VERSION 5.7 ;
BUSBITCHARS "[]" ;
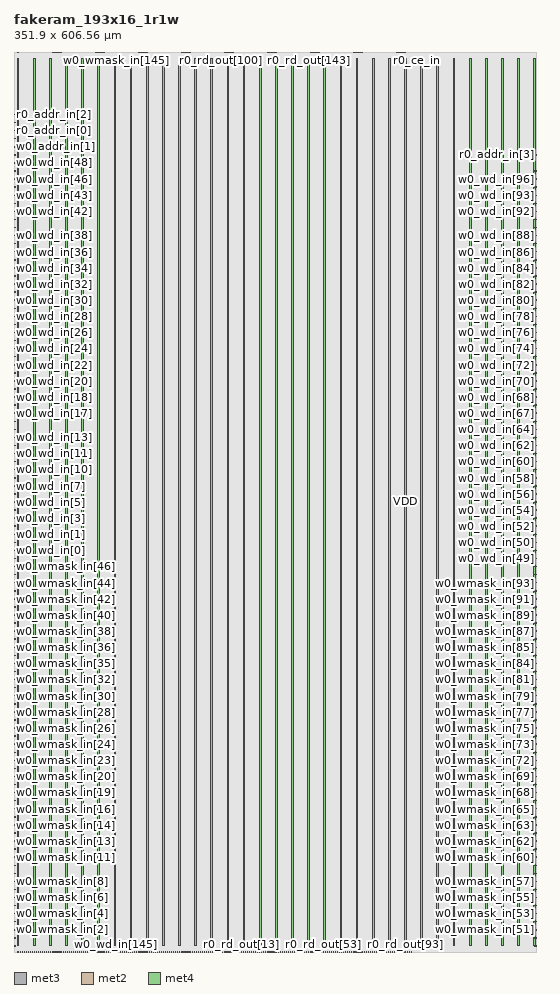
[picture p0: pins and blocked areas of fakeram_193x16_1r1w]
MACRO fakeram_193x16_1r1w
  FOREIGN fakeram_193x16_1r1w 0 0 ;
  SYMMETRY X Y R90 ;
  SIZE 351.900 BY 606.560 ;
  CLASS BLOCK ;
  PIN w0_wmask_in[0]
    DIRECTION INPUT ;
    USE SIGNAL ;
    SHAPE ABUTMENT ;
    PORT
      LAYER met3 ;
      RECT 0.000 3.930 0.900 4.230 ;
    END
  END w0_wmask_in[0]
  PIN w0_wmask_in[1]
    DIRECTION INPUT ;
    USE SIGNAL ;
    SHAPE ABUTMENT ;
    PORT
      LAYER met3 ;
      RECT 0.000 9.370 0.900 9.670 ;
    END
  END w0_wmask_in[1]
  PIN w0_wmask_in[2]
    DIRECTION INPUT ;
    USE SIGNAL ;
    SHAPE ABUTMENT ;
    PORT
      LAYER met3 ;
      RECT 0.000 14.810 0.900 15.110 ;
    END
  END w0_wmask_in[2]
  PIN w0_wmask_in[3]
    DIRECTION INPUT ;
    USE SIGNAL ;
    SHAPE ABUTMENT ;
    PORT
      LAYER met3 ;
      RECT 0.000 20.250 0.900 20.550 ;
    END
  END w0_wmask_in[3]
  PIN w0_wmask_in[4]
    DIRECTION INPUT ;
    USE SIGNAL ;
    SHAPE ABUTMENT ;
    PORT
      LAYER met3 ;
      RECT 0.000 25.690 0.900 25.990 ;
    END
  END w0_wmask_in[4]
  PIN w0_wmask_in[5]
    DIRECTION INPUT ;
    USE SIGNAL ;
    SHAPE ABUTMENT ;
    PORT
      LAYER met3 ;
      RECT 0.000 31.130 0.900 31.430 ;
    END
  END w0_wmask_in[5]
  PIN w0_wmask_in[6]
    DIRECTION INPUT ;
    USE SIGNAL ;
    SHAPE ABUTMENT ;
    PORT
      LAYER met3 ;
      RECT 0.000 36.570 0.900 36.870 ;
    END
  END w0_wmask_in[6]
  PIN w0_wmask_in[7]
    DIRECTION INPUT ;
    USE SIGNAL ;
    SHAPE ABUTMENT ;
    PORT
      LAYER met3 ;
      RECT 0.000 42.010 0.900 42.310 ;
    END
  END w0_wmask_in[7]
  PIN w0_wmask_in[8]
    DIRECTION INPUT ;
    USE SIGNAL ;
    SHAPE ABUTMENT ;
    PORT
      LAYER met3 ;
      RECT 0.000 47.450 0.900 47.750 ;
    END
  END w0_wmask_in[8]
  PIN w0_wmask_in[9]
    DIRECTION INPUT ;
    USE SIGNAL ;
    SHAPE ABUTMENT ;
    PORT
      LAYER met3 ;
      RECT 0.000 52.890 0.900 53.190 ;
    END
  END w0_wmask_in[9]
  PIN w0_wmask_in[10]
    DIRECTION INPUT ;
    USE SIGNAL ;
    SHAPE ABUTMENT ;
    PORT
      LAYER met3 ;
      RECT 0.000 58.330 0.900 58.630 ;
    END
  END w0_wmask_in[10]
  PIN w0_wmask_in[11]
    DIRECTION INPUT ;
    USE SIGNAL ;
    SHAPE ABUTMENT ;
    PORT
      LAYER met3 ;
      RECT 0.000 63.770 0.900 64.070 ;
    END
  END w0_wmask_in[11]
  PIN w0_wmask_in[12]
    DIRECTION INPUT ;
    USE SIGNAL ;
    SHAPE ABUTMENT ;
    PORT
      LAYER met3 ;
      RECT 0.000 69.210 0.900 69.510 ;
    END
  END w0_wmask_in[12]
  PIN w0_wmask_in[13]
    DIRECTION INPUT ;
    USE SIGNAL ;
    SHAPE ABUTMENT ;
    PORT
      LAYER met3 ;
      RECT 0.000 74.650 0.900 74.950 ;
    END
  END w0_wmask_in[13]
  PIN w0_wmask_in[14]
    DIRECTION INPUT ;
    USE SIGNAL ;
    SHAPE ABUTMENT ;
    PORT
      LAYER met3 ;
      RECT 0.000 80.090 0.900 80.390 ;
    END
  END w0_wmask_in[14]
  PIN w0_wmask_in[15]
    DIRECTION INPUT ;
    USE SIGNAL ;
    SHAPE ABUTMENT ;
    PORT
      LAYER met3 ;
      RECT 0.000 85.530 0.900 85.830 ;
    END
  END w0_wmask_in[15]
  PIN w0_wmask_in[16]
    DIRECTION INPUT ;
    USE SIGNAL ;
    SHAPE ABUTMENT ;
    PORT
      LAYER met3 ;
      RECT 0.000 90.970 0.900 91.270 ;
    END
  END w0_wmask_in[16]
  PIN w0_wmask_in[17]
    DIRECTION INPUT ;
    USE SIGNAL ;
    SHAPE ABUTMENT ;
    PORT
      LAYER met3 ;
      RECT 0.000 96.410 0.900 96.710 ;
    END
  END w0_wmask_in[17]
  PIN w0_wmask_in[18]
    DIRECTION INPUT ;
    USE SIGNAL ;
    SHAPE ABUTMENT ;
    PORT
      LAYER met3 ;
      RECT 0.000 101.850 0.900 102.150 ;
    END
  END w0_wmask_in[18]
  PIN w0_wmask_in[19]
    DIRECTION INPUT ;
    USE SIGNAL ;
    SHAPE ABUTMENT ;
    PORT
      LAYER met3 ;
      RECT 0.000 107.290 0.900 107.590 ;
    END
  END w0_wmask_in[19]
  PIN w0_wmask_in[20]
    DIRECTION INPUT ;
    USE SIGNAL ;
    SHAPE ABUTMENT ;
    PORT
      LAYER met3 ;
      RECT 0.000 112.730 0.900 113.030 ;
    END
  END w0_wmask_in[20]
  PIN w0_wmask_in[21]
    DIRECTION INPUT ;
    USE SIGNAL ;
    SHAPE ABUTMENT ;
    PORT
      LAYER met3 ;
      RECT 0.000 118.170 0.900 118.470 ;
    END
  END w0_wmask_in[21]
  PIN w0_wmask_in[22]
    DIRECTION INPUT ;
    USE SIGNAL ;
    SHAPE ABUTMENT ;
    PORT
      LAYER met3 ;
      RECT 0.000 123.610 0.900 123.910 ;
    END
  END w0_wmask_in[22]
  PIN w0_wmask_in[23]
    DIRECTION INPUT ;
    USE SIGNAL ;
    SHAPE ABUTMENT ;
    PORT
      LAYER met3 ;
      RECT 0.000 129.050 0.900 129.350 ;
    END
  END w0_wmask_in[23]
  PIN w0_wmask_in[24]
    DIRECTION INPUT ;
    USE SIGNAL ;
    SHAPE ABUTMENT ;
    PORT
      LAYER met3 ;
      RECT 0.000 134.490 0.900 134.790 ;
    END
  END w0_wmask_in[24]
  PIN w0_wmask_in[25]
    DIRECTION INPUT ;
    USE SIGNAL ;
    SHAPE ABUTMENT ;
    PORT
      LAYER met3 ;
      RECT 0.000 139.930 0.900 140.230 ;
    END
  END w0_wmask_in[25]
  PIN w0_wmask_in[26]
    DIRECTION INPUT ;
    USE SIGNAL ;
    SHAPE ABUTMENT ;
    PORT
      LAYER met3 ;
      RECT 0.000 145.370 0.900 145.670 ;
    END
  END w0_wmask_in[26]
  PIN w0_wmask_in[27]
    DIRECTION INPUT ;
    USE SIGNAL ;
    SHAPE ABUTMENT ;
    PORT
      LAYER met3 ;
      RECT 0.000 150.810 0.900 151.110 ;
    END
  END w0_wmask_in[27]
  PIN w0_wmask_in[28]
    DIRECTION INPUT ;
    USE SIGNAL ;
    SHAPE ABUTMENT ;
    PORT
      LAYER met3 ;
      RECT 0.000 156.250 0.900 156.550 ;
    END
  END w0_wmask_in[28]
  PIN w0_wmask_in[29]
    DIRECTION INPUT ;
    USE SIGNAL ;
    SHAPE ABUTMENT ;
    PORT
      LAYER met3 ;
      RECT 0.000 161.690 0.900 161.990 ;
    END
  END w0_wmask_in[29]
  PIN w0_wmask_in[30]
    DIRECTION INPUT ;
    USE SIGNAL ;
    SHAPE ABUTMENT ;
    PORT
      LAYER met3 ;
      RECT 0.000 167.130 0.900 167.430 ;
    END
  END w0_wmask_in[30]
  PIN w0_wmask_in[31]
    DIRECTION INPUT ;
    USE SIGNAL ;
    SHAPE ABUTMENT ;
    PORT
      LAYER met3 ;
      RECT 0.000 172.570 0.900 172.870 ;
    END
  END w0_wmask_in[31]
  PIN w0_wmask_in[32]
    DIRECTION INPUT ;
    USE SIGNAL ;
    SHAPE ABUTMENT ;
    PORT
      LAYER met3 ;
      RECT 0.000 178.010 0.900 178.310 ;
    END
  END w0_wmask_in[32]
  PIN w0_wmask_in[33]
    DIRECTION INPUT ;
    USE SIGNAL ;
    SHAPE ABUTMENT ;
    PORT
      LAYER met3 ;
      RECT 0.000 183.450 0.900 183.750 ;
    END
  END w0_wmask_in[33]
  PIN w0_wmask_in[34]
    DIRECTION INPUT ;
    USE SIGNAL ;
    SHAPE ABUTMENT ;
    PORT
      LAYER met3 ;
      RECT 0.000 188.890 0.900 189.190 ;
    END
  END w0_wmask_in[34]
  PIN w0_wmask_in[35]
    DIRECTION INPUT ;
    USE SIGNAL ;
    SHAPE ABUTMENT ;
    PORT
      LAYER met3 ;
      RECT 0.000 194.330 0.900 194.630 ;
    END
  END w0_wmask_in[35]
  PIN w0_wmask_in[36]
    DIRECTION INPUT ;
    USE SIGNAL ;
    SHAPE ABUTMENT ;
    PORT
      LAYER met3 ;
      RECT 0.000 199.770 0.900 200.070 ;
    END
  END w0_wmask_in[36]
  PIN w0_wmask_in[37]
    DIRECTION INPUT ;
    USE SIGNAL ;
    SHAPE ABUTMENT ;
    PORT
      LAYER met3 ;
      RECT 0.000 205.210 0.900 205.510 ;
    END
  END w0_wmask_in[37]
  PIN w0_wmask_in[38]
    DIRECTION INPUT ;
    USE SIGNAL ;
    SHAPE ABUTMENT ;
    PORT
      LAYER met3 ;
      RECT 0.000 210.650 0.900 210.950 ;
    END
  END w0_wmask_in[38]
  PIN w0_wmask_in[39]
    DIRECTION INPUT ;
    USE SIGNAL ;
    SHAPE ABUTMENT ;
    PORT
      LAYER met3 ;
      RECT 0.000 216.090 0.900 216.390 ;
    END
  END w0_wmask_in[39]
  PIN w0_wmask_in[40]
    DIRECTION INPUT ;
    USE SIGNAL ;
    SHAPE ABUTMENT ;
    PORT
      LAYER met3 ;
      RECT 0.000 221.530 0.900 221.830 ;
    END
  END w0_wmask_in[40]
  PIN w0_wmask_in[41]
    DIRECTION INPUT ;
    USE SIGNAL ;
    SHAPE ABUTMENT ;
    PORT
      LAYER met3 ;
      RECT 0.000 226.970 0.900 227.270 ;
    END
  END w0_wmask_in[41]
  PIN w0_wmask_in[42]
    DIRECTION INPUT ;
    USE SIGNAL ;
    SHAPE ABUTMENT ;
    PORT
      LAYER met3 ;
      RECT 0.000 232.410 0.900 232.710 ;
    END
  END w0_wmask_in[42]
  PIN w0_wmask_in[43]
    DIRECTION INPUT ;
    USE SIGNAL ;
    SHAPE ABUTMENT ;
    PORT
      LAYER met3 ;
      RECT 0.000 237.850 0.900 238.150 ;
    END
  END w0_wmask_in[43]
  PIN w0_wmask_in[44]
    DIRECTION INPUT ;
    USE SIGNAL ;
    SHAPE ABUTMENT ;
    PORT
      LAYER met3 ;
      RECT 0.000 243.290 0.900 243.590 ;
    END
  END w0_wmask_in[44]
  PIN w0_wmask_in[45]
    DIRECTION INPUT ;
    USE SIGNAL ;
    SHAPE ABUTMENT ;
    PORT
      LAYER met3 ;
      RECT 0.000 248.730 0.900 249.030 ;
    END
  END w0_wmask_in[45]
  PIN w0_wmask_in[46]
    DIRECTION INPUT ;
    USE SIGNAL ;
    SHAPE ABUTMENT ;
    PORT
      LAYER met3 ;
      RECT 0.000 254.170 0.900 254.470 ;
    END
  END w0_wmask_in[46]
  PIN w0_wmask_in[47]
    DIRECTION INPUT ;
    USE SIGNAL ;
    SHAPE ABUTMENT ;
    PORT
      LAYER met3 ;
      RECT 0.000 259.610 0.900 259.910 ;
    END
  END w0_wmask_in[47]
  PIN w0_wmask_in[48]
    DIRECTION INPUT ;
    USE SIGNAL ;
    SHAPE ABUTMENT ;
    PORT
      LAYER met3 ;
      RECT 0.000 265.050 0.900 265.350 ;
    END
  END w0_wmask_in[48]
  PIN w0_wmask_in[49]
    DIRECTION INPUT ;
    USE SIGNAL ;
    SHAPE ABUTMENT ;
    PORT
      LAYER met3 ;
      RECT 351.000 3.930 351.900 4.230 ;
    END
  END w0_wmask_in[49]
  PIN w0_wmask_in[50]
    DIRECTION INPUT ;
    USE SIGNAL ;
    SHAPE ABUTMENT ;
    PORT
      LAYER met3 ;
      RECT 351.000 9.370 351.900 9.670 ;
    END
  END w0_wmask_in[50]
  PIN w0_wmask_in[51]
    DIRECTION INPUT ;
    USE SIGNAL ;
    SHAPE ABUTMENT ;
    PORT
      LAYER met3 ;
      RECT 351.000 14.810 351.900 15.110 ;
    END
  END w0_wmask_in[51]
  PIN w0_wmask_in[52]
    DIRECTION INPUT ;
    USE SIGNAL ;
    SHAPE ABUTMENT ;
    PORT
      LAYER met3 ;
      RECT 351.000 20.250 351.900 20.550 ;
    END
  END w0_wmask_in[52]
  PIN w0_wmask_in[53]
    DIRECTION INPUT ;
    USE SIGNAL ;
    SHAPE ABUTMENT ;
    PORT
      LAYER met3 ;
      RECT 351.000 25.690 351.900 25.990 ;
    END
  END w0_wmask_in[53]
  PIN w0_wmask_in[54]
    DIRECTION INPUT ;
    USE SIGNAL ;
    SHAPE ABUTMENT ;
    PORT
      LAYER met3 ;
      RECT 351.000 31.130 351.900 31.430 ;
    END
  END w0_wmask_in[54]
  PIN w0_wmask_in[55]
    DIRECTION INPUT ;
    USE SIGNAL ;
    SHAPE ABUTMENT ;
    PORT
      LAYER met3 ;
      RECT 351.000 36.570 351.900 36.870 ;
    END
  END w0_wmask_in[55]
  PIN w0_wmask_in[56]
    DIRECTION INPUT ;
    USE SIGNAL ;
    SHAPE ABUTMENT ;
    PORT
      LAYER met3 ;
      RECT 351.000 42.010 351.900 42.310 ;
    END
  END w0_wmask_in[56]
  PIN w0_wmask_in[57]
    DIRECTION INPUT ;
    USE SIGNAL ;
    SHAPE ABUTMENT ;
    PORT
      LAYER met3 ;
      RECT 351.000 47.450 351.900 47.750 ;
    END
  END w0_wmask_in[57]
  PIN w0_wmask_in[58]
    DIRECTION INPUT ;
    USE SIGNAL ;
    SHAPE ABUTMENT ;
    PORT
      LAYER met3 ;
      RECT 351.000 52.890 351.900 53.190 ;
    END
  END w0_wmask_in[58]
  PIN w0_wmask_in[59]
    DIRECTION INPUT ;
    USE SIGNAL ;
    SHAPE ABUTMENT ;
    PORT
      LAYER met3 ;
      RECT 351.000 58.330 351.900 58.630 ;
    END
  END w0_wmask_in[59]
  PIN w0_wmask_in[60]
    DIRECTION INPUT ;
    USE SIGNAL ;
    SHAPE ABUTMENT ;
    PORT
      LAYER met3 ;
      RECT 351.000 63.770 351.900 64.070 ;
    END
  END w0_wmask_in[60]
  PIN w0_wmask_in[61]
    DIRECTION INPUT ;
    USE SIGNAL ;
    SHAPE ABUTMENT ;
    PORT
      LAYER met3 ;
      RECT 351.000 69.210 351.900 69.510 ;
    END
  END w0_wmask_in[61]
  PIN w0_wmask_in[62]
    DIRECTION INPUT ;
    USE SIGNAL ;
    SHAPE ABUTMENT ;
    PORT
      LAYER met3 ;
      RECT 351.000 74.650 351.900 74.950 ;
    END
  END w0_wmask_in[62]
  PIN w0_wmask_in[63]
    DIRECTION INPUT ;
    USE SIGNAL ;
    SHAPE ABUTMENT ;
    PORT
      LAYER met3 ;
      RECT 351.000 80.090 351.900 80.390 ;
    END
  END w0_wmask_in[63]
  PIN w0_wmask_in[64]
    DIRECTION INPUT ;
    USE SIGNAL ;
    SHAPE ABUTMENT ;
    PORT
      LAYER met3 ;
      RECT 351.000 85.530 351.900 85.830 ;
    END
  END w0_wmask_in[64]
  PIN w0_wmask_in[65]
    DIRECTION INPUT ;
    USE SIGNAL ;
    SHAPE ABUTMENT ;
    PORT
      LAYER met3 ;
      RECT 351.000 90.970 351.900 91.270 ;
    END
  END w0_wmask_in[65]
  PIN w0_wmask_in[66]
    DIRECTION INPUT ;
    USE SIGNAL ;
    SHAPE ABUTMENT ;
    PORT
      LAYER met3 ;
      RECT 351.000 96.410 351.900 96.710 ;
    END
  END w0_wmask_in[66]
  PIN w0_wmask_in[67]
    DIRECTION INPUT ;
    USE SIGNAL ;
    SHAPE ABUTMENT ;
    PORT
      LAYER met3 ;
      RECT 351.000 101.850 351.900 102.150 ;
    END
  END w0_wmask_in[67]
  PIN w0_wmask_in[68]
    DIRECTION INPUT ;
    USE SIGNAL ;
    SHAPE ABUTMENT ;
    PORT
      LAYER met3 ;
      RECT 351.000 107.290 351.900 107.590 ;
    END
  END w0_wmask_in[68]
  PIN w0_wmask_in[69]
    DIRECTION INPUT ;
    USE SIGNAL ;
    SHAPE ABUTMENT ;
    PORT
      LAYER met3 ;
      RECT 351.000 112.730 351.900 113.030 ;
    END
  END w0_wmask_in[69]
  PIN w0_wmask_in[70]
    DIRECTION INPUT ;
    USE SIGNAL ;
    SHAPE ABUTMENT ;
    PORT
      LAYER met3 ;
      RECT 351.000 118.170 351.900 118.470 ;
    END
  END w0_wmask_in[70]
  PIN w0_wmask_in[71]
    DIRECTION INPUT ;
    USE SIGNAL ;
    SHAPE ABUTMENT ;
    PORT
      LAYER met3 ;
      RECT 351.000 123.610 351.900 123.910 ;
    END
  END w0_wmask_in[71]
  PIN w0_wmask_in[72]
    DIRECTION INPUT ;
    USE SIGNAL ;
    SHAPE ABUTMENT ;
    PORT
      LAYER met3 ;
      RECT 351.000 129.050 351.900 129.350 ;
    END
  END w0_wmask_in[72]
  PIN w0_wmask_in[73]
    DIRECTION INPUT ;
    USE SIGNAL ;
    SHAPE ABUTMENT ;
    PORT
      LAYER met3 ;
      RECT 351.000 134.490 351.900 134.790 ;
    END
  END w0_wmask_in[73]
  PIN w0_wmask_in[74]
    DIRECTION INPUT ;
    USE SIGNAL ;
    SHAPE ABUTMENT ;
    PORT
      LAYER met3 ;
      RECT 351.000 139.930 351.900 140.230 ;
    END
  END w0_wmask_in[74]
  PIN w0_wmask_in[75]
    DIRECTION INPUT ;
    USE SIGNAL ;
    SHAPE ABUTMENT ;
    PORT
      LAYER met3 ;
      RECT 351.000 145.370 351.900 145.670 ;
    END
  END w0_wmask_in[75]
  PIN w0_wmask_in[76]
    DIRECTION INPUT ;
    USE SIGNAL ;
    SHAPE ABUTMENT ;
    PORT
      LAYER met3 ;
      RECT 351.000 150.810 351.900 151.110 ;
    END
  END w0_wmask_in[76]
  PIN w0_wmask_in[77]
    DIRECTION INPUT ;
    USE SIGNAL ;
    SHAPE ABUTMENT ;
    PORT
      LAYER met3 ;
      RECT 351.000 156.250 351.900 156.550 ;
    END
  END w0_wmask_in[77]
  PIN w0_wmask_in[78]
    DIRECTION INPUT ;
    USE SIGNAL ;
    SHAPE ABUTMENT ;
    PORT
      LAYER met3 ;
      RECT 351.000 161.690 351.900 161.990 ;
    END
  END w0_wmask_in[78]
  PIN w0_wmask_in[79]
    DIRECTION INPUT ;
    USE SIGNAL ;
    SHAPE ABUTMENT ;
    PORT
      LAYER met3 ;
      RECT 351.000 167.130 351.900 167.430 ;
    END
  END w0_wmask_in[79]
  PIN w0_wmask_in[80]
    DIRECTION INPUT ;
    USE SIGNAL ;
    SHAPE ABUTMENT ;
    PORT
      LAYER met3 ;
      RECT 351.000 172.570 351.900 172.870 ;
    END
  END w0_wmask_in[80]
  PIN w0_wmask_in[81]
    DIRECTION INPUT ;
    USE SIGNAL ;
    SHAPE ABUTMENT ;
    PORT
      LAYER met3 ;
      RECT 351.000 178.010 351.900 178.310 ;
    END
  END w0_wmask_in[81]
  PIN w0_wmask_in[82]
    DIRECTION INPUT ;
    USE SIGNAL ;
    SHAPE ABUTMENT ;
    PORT
      LAYER met3 ;
      RECT 351.000 183.450 351.900 183.750 ;
    END
  END w0_wmask_in[82]
  PIN w0_wmask_in[83]
    DIRECTION INPUT ;
    USE SIGNAL ;
    SHAPE ABUTMENT ;
    PORT
      LAYER met3 ;
      RECT 351.000 188.890 351.900 189.190 ;
    END
  END w0_wmask_in[83]
  PIN w0_wmask_in[84]
    DIRECTION INPUT ;
    USE SIGNAL ;
    SHAPE ABUTMENT ;
    PORT
      LAYER met3 ;
      RECT 351.000 194.330 351.900 194.630 ;
    END
  END w0_wmask_in[84]
  PIN w0_wmask_in[85]
    DIRECTION INPUT ;
    USE SIGNAL ;
    SHAPE ABUTMENT ;
    PORT
      LAYER met3 ;
      RECT 351.000 199.770 351.900 200.070 ;
    END
  END w0_wmask_in[85]
  PIN w0_wmask_in[86]
    DIRECTION INPUT ;
    USE SIGNAL ;
    SHAPE ABUTMENT ;
    PORT
      LAYER met3 ;
      RECT 351.000 205.210 351.900 205.510 ;
    END
  END w0_wmask_in[86]
  PIN w0_wmask_in[87]
    DIRECTION INPUT ;
    USE SIGNAL ;
    SHAPE ABUTMENT ;
    PORT
      LAYER met3 ;
      RECT 351.000 210.650 351.900 210.950 ;
    END
  END w0_wmask_in[87]
  PIN w0_wmask_in[88]
    DIRECTION INPUT ;
    USE SIGNAL ;
    SHAPE ABUTMENT ;
    PORT
      LAYER met3 ;
      RECT 351.000 216.090 351.900 216.390 ;
    END
  END w0_wmask_in[88]
  PIN w0_wmask_in[89]
    DIRECTION INPUT ;
    USE SIGNAL ;
    SHAPE ABUTMENT ;
    PORT
      LAYER met3 ;
      RECT 351.000 221.530 351.900 221.830 ;
    END
  END w0_wmask_in[89]
  PIN w0_wmask_in[90]
    DIRECTION INPUT ;
    USE SIGNAL ;
    SHAPE ABUTMENT ;
    PORT
      LAYER met3 ;
      RECT 351.000 226.970 351.900 227.270 ;
    END
  END w0_wmask_in[90]
  PIN w0_wmask_in[91]
    DIRECTION INPUT ;
    USE SIGNAL ;
    SHAPE ABUTMENT ;
    PORT
      LAYER met3 ;
      RECT 351.000 232.410 351.900 232.710 ;
    END
  END w0_wmask_in[91]
  PIN w0_wmask_in[92]
    DIRECTION INPUT ;
    USE SIGNAL ;
    SHAPE ABUTMENT ;
    PORT
      LAYER met3 ;
      RECT 351.000 237.850 351.900 238.150 ;
    END
  END w0_wmask_in[92]
  PIN w0_wmask_in[93]
    DIRECTION INPUT ;
    USE SIGNAL ;
    SHAPE ABUTMENT ;
    PORT
      LAYER met3 ;
      RECT 351.000 243.290 351.900 243.590 ;
    END
  END w0_wmask_in[93]
  PIN w0_wmask_in[94]
    DIRECTION INPUT ;
    USE SIGNAL ;
    SHAPE ABUTMENT ;
    PORT
      LAYER met3 ;
      RECT 351.000 248.730 351.900 249.030 ;
    END
  END w0_wmask_in[94]
  PIN w0_wmask_in[95]
    DIRECTION INPUT ;
    USE SIGNAL ;
    SHAPE ABUTMENT ;
    PORT
      LAYER met3 ;
      RECT 351.000 254.170 351.900 254.470 ;
    END
  END w0_wmask_in[95]
  PIN w0_wmask_in[96]
    DIRECTION INPUT ;
    USE SIGNAL ;
    SHAPE ABUTMENT ;
    PORT
      LAYER met3 ;
      RECT 351.000 259.610 351.900 259.910 ;
    END
  END w0_wmask_in[96]
  PIN w0_wmask_in[97]
    DIRECTION INPUT ;
    USE SIGNAL ;
    SHAPE ABUTMENT ;
    PORT
      LAYER met2 ;
      RECT 2.690 606.140 2.830 606.560 ;
    END
  END w0_wmask_in[97]
  PIN w0_wmask_in[98]
    DIRECTION INPUT ;
    USE SIGNAL ;
    SHAPE ABUTMENT ;
    PORT
      LAYER met2 ;
      RECT 4.070 606.140 4.210 606.560 ;
    END
  END w0_wmask_in[98]
  PIN w0_wmask_in[99]
    DIRECTION INPUT ;
    USE SIGNAL ;
    SHAPE ABUTMENT ;
    PORT
      LAYER met2 ;
      RECT 5.450 606.140 5.590 606.560 ;
    END
  END w0_wmask_in[99]
  PIN w0_wmask_in[100]
    DIRECTION INPUT ;
    USE SIGNAL ;
    SHAPE ABUTMENT ;
    PORT
      LAYER met2 ;
      RECT 6.830 606.140 6.970 606.560 ;
    END
  END w0_wmask_in[100]
  PIN w0_wmask_in[101]
    DIRECTION INPUT ;
    USE SIGNAL ;
    SHAPE ABUTMENT ;
    PORT
      LAYER met2 ;
      RECT 8.210 606.140 8.350 606.560 ;
    END
  END w0_wmask_in[101]
  PIN w0_wmask_in[102]
    DIRECTION INPUT ;
    USE SIGNAL ;
    SHAPE ABUTMENT ;
    PORT
      LAYER met2 ;
      RECT 9.590 606.140 9.730 606.560 ;
    END
  END w0_wmask_in[102]
  PIN w0_wmask_in[103]
    DIRECTION INPUT ;
    USE SIGNAL ;
    SHAPE ABUTMENT ;
    PORT
      LAYER met2 ;
      RECT 10.970 606.140 11.110 606.560 ;
    END
  END w0_wmask_in[103]
  PIN w0_wmask_in[104]
    DIRECTION INPUT ;
    USE SIGNAL ;
    SHAPE ABUTMENT ;
    PORT
      LAYER met2 ;
      RECT 12.350 606.140 12.490 606.560 ;
    END
  END w0_wmask_in[104]
  PIN w0_wmask_in[105]
    DIRECTION INPUT ;
    USE SIGNAL ;
    SHAPE ABUTMENT ;
    PORT
      LAYER met2 ;
      RECT 13.730 606.140 13.870 606.560 ;
    END
  END w0_wmask_in[105]
  PIN w0_wmask_in[106]
    DIRECTION INPUT ;
    USE SIGNAL ;
    SHAPE ABUTMENT ;
    PORT
      LAYER met2 ;
      RECT 15.110 606.140 15.250 606.560 ;
    END
  END w0_wmask_in[106]
  PIN w0_wmask_in[107]
    DIRECTION INPUT ;
    USE SIGNAL ;
    SHAPE ABUTMENT ;
    PORT
      LAYER met2 ;
      RECT 16.490 606.140 16.630 606.560 ;
    END
  END w0_wmask_in[107]
  PIN w0_wmask_in[108]
    DIRECTION INPUT ;
    USE SIGNAL ;
    SHAPE ABUTMENT ;
    PORT
      LAYER met2 ;
      RECT 17.870 606.140 18.010 606.560 ;
    END
  END w0_wmask_in[108]
  PIN w0_wmask_in[109]
    DIRECTION INPUT ;
    USE SIGNAL ;
    SHAPE ABUTMENT ;
    PORT
      LAYER met2 ;
      RECT 19.250 606.140 19.390 606.560 ;
    END
  END w0_wmask_in[109]
  PIN w0_wmask_in[110]
    DIRECTION INPUT ;
    USE SIGNAL ;
    SHAPE ABUTMENT ;
    PORT
      LAYER met2 ;
      RECT 20.630 606.140 20.770 606.560 ;
    END
  END w0_wmask_in[110]
  PIN w0_wmask_in[111]
    DIRECTION INPUT ;
    USE SIGNAL ;
    SHAPE ABUTMENT ;
    PORT
      LAYER met2 ;
      RECT 22.010 606.140 22.150 606.560 ;
    END
  END w0_wmask_in[111]
  PIN w0_wmask_in[112]
    DIRECTION INPUT ;
    USE SIGNAL ;
    SHAPE ABUTMENT ;
    PORT
      LAYER met2 ;
      RECT 23.390 606.140 23.530 606.560 ;
    END
  END w0_wmask_in[112]
  PIN w0_wmask_in[113]
    DIRECTION INPUT ;
    USE SIGNAL ;
    SHAPE ABUTMENT ;
    PORT
      LAYER met2 ;
      RECT 24.770 606.140 24.910 606.560 ;
    END
  END w0_wmask_in[113]
  PIN w0_wmask_in[114]
    DIRECTION INPUT ;
    USE SIGNAL ;
    SHAPE ABUTMENT ;
    PORT
      LAYER met2 ;
      RECT 26.150 606.140 26.290 606.560 ;
    END
  END w0_wmask_in[114]
  PIN w0_wmask_in[115]
    DIRECTION INPUT ;
    USE SIGNAL ;
    SHAPE ABUTMENT ;
    PORT
      LAYER met2 ;
      RECT 27.530 606.140 27.670 606.560 ;
    END
  END w0_wmask_in[115]
  PIN w0_wmask_in[116]
    DIRECTION INPUT ;
    USE SIGNAL ;
    SHAPE ABUTMENT ;
    PORT
      LAYER met2 ;
      RECT 28.910 606.140 29.050 606.560 ;
    END
  END w0_wmask_in[116]
  PIN w0_wmask_in[117]
    DIRECTION INPUT ;
    USE SIGNAL ;
    SHAPE ABUTMENT ;
    PORT
      LAYER met2 ;
      RECT 30.290 606.140 30.430 606.560 ;
    END
  END w0_wmask_in[117]
  PIN w0_wmask_in[118]
    DIRECTION INPUT ;
    USE SIGNAL ;
    SHAPE ABUTMENT ;
    PORT
      LAYER met2 ;
      RECT 31.670 606.140 31.810 606.560 ;
    END
  END w0_wmask_in[118]
  PIN w0_wmask_in[119]
    DIRECTION INPUT ;
    USE SIGNAL ;
    SHAPE ABUTMENT ;
    PORT
      LAYER met2 ;
      RECT 33.050 606.140 33.190 606.560 ;
    END
  END w0_wmask_in[119]
  PIN w0_wmask_in[120]
    DIRECTION INPUT ;
    USE SIGNAL ;
    SHAPE ABUTMENT ;
    PORT
      LAYER met2 ;
      RECT 34.430 606.140 34.570 606.560 ;
    END
  END w0_wmask_in[120]
  PIN w0_wmask_in[121]
    DIRECTION INPUT ;
    USE SIGNAL ;
    SHAPE ABUTMENT ;
    PORT
      LAYER met2 ;
      RECT 35.810 606.140 35.950 606.560 ;
    END
  END w0_wmask_in[121]
  PIN w0_wmask_in[122]
    DIRECTION INPUT ;
    USE SIGNAL ;
    SHAPE ABUTMENT ;
    PORT
      LAYER met2 ;
      RECT 37.190 606.140 37.330 606.560 ;
    END
  END w0_wmask_in[122]
  PIN w0_wmask_in[123]
    DIRECTION INPUT ;
    USE SIGNAL ;
    SHAPE ABUTMENT ;
    PORT
      LAYER met2 ;
      RECT 38.570 606.140 38.710 606.560 ;
    END
  END w0_wmask_in[123]
  PIN w0_wmask_in[124]
    DIRECTION INPUT ;
    USE SIGNAL ;
    SHAPE ABUTMENT ;
    PORT
      LAYER met2 ;
      RECT 39.950 606.140 40.090 606.560 ;
    END
  END w0_wmask_in[124]
  PIN w0_wmask_in[125]
    DIRECTION INPUT ;
    USE SIGNAL ;
    SHAPE ABUTMENT ;
    PORT
      LAYER met2 ;
      RECT 41.330 606.140 41.470 606.560 ;
    END
  END w0_wmask_in[125]
  PIN w0_wmask_in[126]
    DIRECTION INPUT ;
    USE SIGNAL ;
    SHAPE ABUTMENT ;
    PORT
      LAYER met2 ;
      RECT 42.710 606.140 42.850 606.560 ;
    END
  END w0_wmask_in[126]
  PIN w0_wmask_in[127]
    DIRECTION INPUT ;
    USE SIGNAL ;
    SHAPE ABUTMENT ;
    PORT
      LAYER met2 ;
      RECT 44.090 606.140 44.230 606.560 ;
    END
  END w0_wmask_in[127]
  PIN w0_wmask_in[128]
    DIRECTION INPUT ;
    USE SIGNAL ;
    SHAPE ABUTMENT ;
    PORT
      LAYER met2 ;
      RECT 45.470 606.140 45.610 606.560 ;
    END
  END w0_wmask_in[128]
  PIN w0_wmask_in[129]
    DIRECTION INPUT ;
    USE SIGNAL ;
    SHAPE ABUTMENT ;
    PORT
      LAYER met2 ;
      RECT 46.850 606.140 46.990 606.560 ;
    END
  END w0_wmask_in[129]
  PIN w0_wmask_in[130]
    DIRECTION INPUT ;
    USE SIGNAL ;
    SHAPE ABUTMENT ;
    PORT
      LAYER met2 ;
      RECT 48.230 606.140 48.370 606.560 ;
    END
  END w0_wmask_in[130]
  PIN w0_wmask_in[131]
    DIRECTION INPUT ;
    USE SIGNAL ;
    SHAPE ABUTMENT ;
    PORT
      LAYER met2 ;
      RECT 49.610 606.140 49.750 606.560 ;
    END
  END w0_wmask_in[131]
  PIN w0_wmask_in[132]
    DIRECTION INPUT ;
    USE SIGNAL ;
    SHAPE ABUTMENT ;
    PORT
      LAYER met2 ;
      RECT 50.990 606.140 51.130 606.560 ;
    END
  END w0_wmask_in[132]
  PIN w0_wmask_in[133]
    DIRECTION INPUT ;
    USE SIGNAL ;
    SHAPE ABUTMENT ;
    PORT
      LAYER met2 ;
      RECT 52.370 606.140 52.510 606.560 ;
    END
  END w0_wmask_in[133]
  PIN w0_wmask_in[134]
    DIRECTION INPUT ;
    USE SIGNAL ;
    SHAPE ABUTMENT ;
    PORT
      LAYER met2 ;
      RECT 53.750 606.140 53.890 606.560 ;
    END
  END w0_wmask_in[134]
  PIN w0_wmask_in[135]
    DIRECTION INPUT ;
    USE SIGNAL ;
    SHAPE ABUTMENT ;
    PORT
      LAYER met2 ;
      RECT 55.130 606.140 55.270 606.560 ;
    END
  END w0_wmask_in[135]
  PIN w0_wmask_in[136]
    DIRECTION INPUT ;
    USE SIGNAL ;
    SHAPE ABUTMENT ;
    PORT
      LAYER met2 ;
      RECT 56.510 606.140 56.650 606.560 ;
    END
  END w0_wmask_in[136]
  PIN w0_wmask_in[137]
    DIRECTION INPUT ;
    USE SIGNAL ;
    SHAPE ABUTMENT ;
    PORT
      LAYER met2 ;
      RECT 57.890 606.140 58.030 606.560 ;
    END
  END w0_wmask_in[137]
  PIN w0_wmask_in[138]
    DIRECTION INPUT ;
    USE SIGNAL ;
    SHAPE ABUTMENT ;
    PORT
      LAYER met2 ;
      RECT 59.270 606.140 59.410 606.560 ;
    END
  END w0_wmask_in[138]
  PIN w0_wmask_in[139]
    DIRECTION INPUT ;
    USE SIGNAL ;
    SHAPE ABUTMENT ;
    PORT
      LAYER met2 ;
      RECT 60.650 606.140 60.790 606.560 ;
    END
  END w0_wmask_in[139]
  PIN w0_wmask_in[140]
    DIRECTION INPUT ;
    USE SIGNAL ;
    SHAPE ABUTMENT ;
    PORT
      LAYER met2 ;
      RECT 62.030 606.140 62.170 606.560 ;
    END
  END w0_wmask_in[140]
  PIN w0_wmask_in[141]
    DIRECTION INPUT ;
    USE SIGNAL ;
    SHAPE ABUTMENT ;
    PORT
      LAYER met2 ;
      RECT 63.410 606.140 63.550 606.560 ;
    END
  END w0_wmask_in[141]
  PIN w0_wmask_in[142]
    DIRECTION INPUT ;
    USE SIGNAL ;
    SHAPE ABUTMENT ;
    PORT
      LAYER met2 ;
      RECT 64.790 606.140 64.930 606.560 ;
    END
  END w0_wmask_in[142]
  PIN w0_wmask_in[143]
    DIRECTION INPUT ;
    USE SIGNAL ;
    SHAPE ABUTMENT ;
    PORT
      LAYER met2 ;
      RECT 66.170 606.140 66.310 606.560 ;
    END
  END w0_wmask_in[143]
  PIN w0_wmask_in[144]
    DIRECTION INPUT ;
    USE SIGNAL ;
    SHAPE ABUTMENT ;
    PORT
      LAYER met2 ;
      RECT 67.550 606.140 67.690 606.560 ;
    END
  END w0_wmask_in[144]
  PIN w0_wmask_in[145]
    DIRECTION INPUT ;
    USE SIGNAL ;
    SHAPE ABUTMENT ;
    PORT
      LAYER met2 ;
      RECT 68.930 606.140 69.070 606.560 ;
    END
  END w0_wmask_in[145]
  PIN w0_wmask_in[146]
    DIRECTION INPUT ;
    USE SIGNAL ;
    SHAPE ABUTMENT ;
    PORT
      LAYER met2 ;
      RECT 70.310 606.140 70.450 606.560 ;
    END
  END w0_wmask_in[146]
  PIN w0_wmask_in[147]
    DIRECTION INPUT ;
    USE SIGNAL ;
    SHAPE ABUTMENT ;
    PORT
      LAYER met2 ;
      RECT 71.690 606.140 71.830 606.560 ;
    END
  END w0_wmask_in[147]
  PIN w0_wmask_in[148]
    DIRECTION INPUT ;
    USE SIGNAL ;
    SHAPE ABUTMENT ;
    PORT
      LAYER met2 ;
      RECT 73.070 606.140 73.210 606.560 ;
    END
  END w0_wmask_in[148]
  PIN w0_wmask_in[149]
    DIRECTION INPUT ;
    USE SIGNAL ;
    SHAPE ABUTMENT ;
    PORT
      LAYER met2 ;
      RECT 74.450 606.140 74.590 606.560 ;
    END
  END w0_wmask_in[149]
  PIN w0_wmask_in[150]
    DIRECTION INPUT ;
    USE SIGNAL ;
    SHAPE ABUTMENT ;
    PORT
      LAYER met2 ;
      RECT 75.830 606.140 75.970 606.560 ;
    END
  END w0_wmask_in[150]
  PIN w0_wmask_in[151]
    DIRECTION INPUT ;
    USE SIGNAL ;
    SHAPE ABUTMENT ;
    PORT
      LAYER met2 ;
      RECT 77.210 606.140 77.350 606.560 ;
    END
  END w0_wmask_in[151]
  PIN w0_wmask_in[152]
    DIRECTION INPUT ;
    USE SIGNAL ;
    SHAPE ABUTMENT ;
    PORT
      LAYER met2 ;
      RECT 78.590 606.140 78.730 606.560 ;
    END
  END w0_wmask_in[152]
  PIN w0_wmask_in[153]
    DIRECTION INPUT ;
    USE SIGNAL ;
    SHAPE ABUTMENT ;
    PORT
      LAYER met2 ;
      RECT 79.970 606.140 80.110 606.560 ;
    END
  END w0_wmask_in[153]
  PIN w0_wmask_in[154]
    DIRECTION INPUT ;
    USE SIGNAL ;
    SHAPE ABUTMENT ;
    PORT
      LAYER met2 ;
      RECT 81.350 606.140 81.490 606.560 ;
    END
  END w0_wmask_in[154]
  PIN w0_wmask_in[155]
    DIRECTION INPUT ;
    USE SIGNAL ;
    SHAPE ABUTMENT ;
    PORT
      LAYER met2 ;
      RECT 82.730 606.140 82.870 606.560 ;
    END
  END w0_wmask_in[155]
  PIN w0_wmask_in[156]
    DIRECTION INPUT ;
    USE SIGNAL ;
    SHAPE ABUTMENT ;
    PORT
      LAYER met2 ;
      RECT 84.110 606.140 84.250 606.560 ;
    END
  END w0_wmask_in[156]
  PIN w0_wmask_in[157]
    DIRECTION INPUT ;
    USE SIGNAL ;
    SHAPE ABUTMENT ;
    PORT
      LAYER met2 ;
      RECT 85.490 606.140 85.630 606.560 ;
    END
  END w0_wmask_in[157]
  PIN w0_wmask_in[158]
    DIRECTION INPUT ;
    USE SIGNAL ;
    SHAPE ABUTMENT ;
    PORT
      LAYER met2 ;
      RECT 86.870 606.140 87.010 606.560 ;
    END
  END w0_wmask_in[158]
  PIN w0_wmask_in[159]
    DIRECTION INPUT ;
    USE SIGNAL ;
    SHAPE ABUTMENT ;
    PORT
      LAYER met2 ;
      RECT 88.250 606.140 88.390 606.560 ;
    END
  END w0_wmask_in[159]
  PIN w0_wmask_in[160]
    DIRECTION INPUT ;
    USE SIGNAL ;
    SHAPE ABUTMENT ;
    PORT
      LAYER met2 ;
      RECT 89.630 606.140 89.770 606.560 ;
    END
  END w0_wmask_in[160]
  PIN w0_wmask_in[161]
    DIRECTION INPUT ;
    USE SIGNAL ;
    SHAPE ABUTMENT ;
    PORT
      LAYER met2 ;
      RECT 91.010 606.140 91.150 606.560 ;
    END
  END w0_wmask_in[161]
  PIN w0_wmask_in[162]
    DIRECTION INPUT ;
    USE SIGNAL ;
    SHAPE ABUTMENT ;
    PORT
      LAYER met2 ;
      RECT 92.390 606.140 92.530 606.560 ;
    END
  END w0_wmask_in[162]
  PIN w0_wmask_in[163]
    DIRECTION INPUT ;
    USE SIGNAL ;
    SHAPE ABUTMENT ;
    PORT
      LAYER met2 ;
      RECT 93.770 606.140 93.910 606.560 ;
    END
  END w0_wmask_in[163]
  PIN w0_wmask_in[164]
    DIRECTION INPUT ;
    USE SIGNAL ;
    SHAPE ABUTMENT ;
    PORT
      LAYER met2 ;
      RECT 95.150 606.140 95.290 606.560 ;
    END
  END w0_wmask_in[164]
  PIN w0_wmask_in[165]
    DIRECTION INPUT ;
    USE SIGNAL ;
    SHAPE ABUTMENT ;
    PORT
      LAYER met2 ;
      RECT 96.530 606.140 96.670 606.560 ;
    END
  END w0_wmask_in[165]
  PIN w0_wmask_in[166]
    DIRECTION INPUT ;
    USE SIGNAL ;
    SHAPE ABUTMENT ;
    PORT
      LAYER met2 ;
      RECT 97.910 606.140 98.050 606.560 ;
    END
  END w0_wmask_in[166]
  PIN w0_wmask_in[167]
    DIRECTION INPUT ;
    USE SIGNAL ;
    SHAPE ABUTMENT ;
    PORT
      LAYER met2 ;
      RECT 99.290 606.140 99.430 606.560 ;
    END
  END w0_wmask_in[167]
  PIN w0_wmask_in[168]
    DIRECTION INPUT ;
    USE SIGNAL ;
    SHAPE ABUTMENT ;
    PORT
      LAYER met2 ;
      RECT 100.670 606.140 100.810 606.560 ;
    END
  END w0_wmask_in[168]
  PIN w0_wmask_in[169]
    DIRECTION INPUT ;
    USE SIGNAL ;
    SHAPE ABUTMENT ;
    PORT
      LAYER met2 ;
      RECT 102.050 606.140 102.190 606.560 ;
    END
  END w0_wmask_in[169]
  PIN w0_wmask_in[170]
    DIRECTION INPUT ;
    USE SIGNAL ;
    SHAPE ABUTMENT ;
    PORT
      LAYER met2 ;
      RECT 103.430 606.140 103.570 606.560 ;
    END
  END w0_wmask_in[170]
  PIN w0_wmask_in[171]
    DIRECTION INPUT ;
    USE SIGNAL ;
    SHAPE ABUTMENT ;
    PORT
      LAYER met2 ;
      RECT 104.810 606.140 104.950 606.560 ;
    END
  END w0_wmask_in[171]
  PIN w0_wmask_in[172]
    DIRECTION INPUT ;
    USE SIGNAL ;
    SHAPE ABUTMENT ;
    PORT
      LAYER met2 ;
      RECT 106.190 606.140 106.330 606.560 ;
    END
  END w0_wmask_in[172]
  PIN w0_wmask_in[173]
    DIRECTION INPUT ;
    USE SIGNAL ;
    SHAPE ABUTMENT ;
    PORT
      LAYER met2 ;
      RECT 107.570 606.140 107.710 606.560 ;
    END
  END w0_wmask_in[173]
  PIN w0_wmask_in[174]
    DIRECTION INPUT ;
    USE SIGNAL ;
    SHAPE ABUTMENT ;
    PORT
      LAYER met2 ;
      RECT 108.950 606.140 109.090 606.560 ;
    END
  END w0_wmask_in[174]
  PIN w0_wmask_in[175]
    DIRECTION INPUT ;
    USE SIGNAL ;
    SHAPE ABUTMENT ;
    PORT
      LAYER met2 ;
      RECT 110.330 606.140 110.470 606.560 ;
    END
  END w0_wmask_in[175]
  PIN w0_wmask_in[176]
    DIRECTION INPUT ;
    USE SIGNAL ;
    SHAPE ABUTMENT ;
    PORT
      LAYER met2 ;
      RECT 111.710 606.140 111.850 606.560 ;
    END
  END w0_wmask_in[176]
  PIN w0_wmask_in[177]
    DIRECTION INPUT ;
    USE SIGNAL ;
    SHAPE ABUTMENT ;
    PORT
      LAYER met2 ;
      RECT 113.090 606.140 113.230 606.560 ;
    END
  END w0_wmask_in[177]
  PIN w0_wmask_in[178]
    DIRECTION INPUT ;
    USE SIGNAL ;
    SHAPE ABUTMENT ;
    PORT
      LAYER met2 ;
      RECT 114.470 606.140 114.610 606.560 ;
    END
  END w0_wmask_in[178]
  PIN w0_wmask_in[179]
    DIRECTION INPUT ;
    USE SIGNAL ;
    SHAPE ABUTMENT ;
    PORT
      LAYER met2 ;
      RECT 115.850 606.140 115.990 606.560 ;
    END
  END w0_wmask_in[179]
  PIN w0_wmask_in[180]
    DIRECTION INPUT ;
    USE SIGNAL ;
    SHAPE ABUTMENT ;
    PORT
      LAYER met2 ;
      RECT 117.230 606.140 117.370 606.560 ;
    END
  END w0_wmask_in[180]
  PIN w0_wmask_in[181]
    DIRECTION INPUT ;
    USE SIGNAL ;
    SHAPE ABUTMENT ;
    PORT
      LAYER met2 ;
      RECT 118.610 606.140 118.750 606.560 ;
    END
  END w0_wmask_in[181]
  PIN w0_wmask_in[182]
    DIRECTION INPUT ;
    USE SIGNAL ;
    SHAPE ABUTMENT ;
    PORT
      LAYER met2 ;
      RECT 119.990 606.140 120.130 606.560 ;
    END
  END w0_wmask_in[182]
  PIN w0_wmask_in[183]
    DIRECTION INPUT ;
    USE SIGNAL ;
    SHAPE ABUTMENT ;
    PORT
      LAYER met2 ;
      RECT 121.370 606.140 121.510 606.560 ;
    END
  END w0_wmask_in[183]
  PIN w0_wmask_in[184]
    DIRECTION INPUT ;
    USE SIGNAL ;
    SHAPE ABUTMENT ;
    PORT
      LAYER met2 ;
      RECT 122.750 606.140 122.890 606.560 ;
    END
  END w0_wmask_in[184]
  PIN w0_wmask_in[185]
    DIRECTION INPUT ;
    USE SIGNAL ;
    SHAPE ABUTMENT ;
    PORT
      LAYER met2 ;
      RECT 124.130 606.140 124.270 606.560 ;
    END
  END w0_wmask_in[185]
  PIN w0_wmask_in[186]
    DIRECTION INPUT ;
    USE SIGNAL ;
    SHAPE ABUTMENT ;
    PORT
      LAYER met2 ;
      RECT 125.510 606.140 125.650 606.560 ;
    END
  END w0_wmask_in[186]
  PIN w0_wmask_in[187]
    DIRECTION INPUT ;
    USE SIGNAL ;
    SHAPE ABUTMENT ;
    PORT
      LAYER met2 ;
      RECT 126.890 606.140 127.030 606.560 ;
    END
  END w0_wmask_in[187]
  PIN w0_wmask_in[188]
    DIRECTION INPUT ;
    USE SIGNAL ;
    SHAPE ABUTMENT ;
    PORT
      LAYER met2 ;
      RECT 128.270 606.140 128.410 606.560 ;
    END
  END w0_wmask_in[188]
  PIN w0_wmask_in[189]
    DIRECTION INPUT ;
    USE SIGNAL ;
    SHAPE ABUTMENT ;
    PORT
      LAYER met2 ;
      RECT 129.650 606.140 129.790 606.560 ;
    END
  END w0_wmask_in[189]
  PIN w0_wmask_in[190]
    DIRECTION INPUT ;
    USE SIGNAL ;
    SHAPE ABUTMENT ;
    PORT
      LAYER met2 ;
      RECT 131.030 606.140 131.170 606.560 ;
    END
  END w0_wmask_in[190]
  PIN w0_wmask_in[191]
    DIRECTION INPUT ;
    USE SIGNAL ;
    SHAPE ABUTMENT ;
    PORT
      LAYER met2 ;
      RECT 132.410 606.140 132.550 606.560 ;
    END
  END w0_wmask_in[191]
  PIN w0_wmask_in[192]
    DIRECTION INPUT ;
    USE SIGNAL ;
    SHAPE ABUTMENT ;
    PORT
      LAYER met2 ;
      RECT 133.790 606.140 133.930 606.560 ;
    END
  END w0_wmask_in[192]
  PIN w0_wd_in[0]
    DIRECTION INPUT ;
    USE SIGNAL ;
    SHAPE ABUTMENT ;
    PORT
      LAYER met3 ;
      RECT 0.000 270.490 0.900 270.790 ;
    END
  END w0_wd_in[0]
  PIN w0_wd_in[1]
    DIRECTION INPUT ;
    USE SIGNAL ;
    SHAPE ABUTMENT ;
    PORT
      LAYER met3 ;
      RECT 0.000 275.930 0.900 276.230 ;
    END
  END w0_wd_in[1]
  PIN w0_wd_in[2]
    DIRECTION INPUT ;
    USE SIGNAL ;
    SHAPE ABUTMENT ;
    PORT
      LAYER met3 ;
      RECT 0.000 281.370 0.900 281.670 ;
    END
  END w0_wd_in[2]
  PIN w0_wd_in[3]
    DIRECTION INPUT ;
    USE SIGNAL ;
    SHAPE ABUTMENT ;
    PORT
      LAYER met3 ;
      RECT 0.000 286.810 0.900 287.110 ;
    END
  END w0_wd_in[3]
  PIN w0_wd_in[4]
    DIRECTION INPUT ;
    USE SIGNAL ;
    SHAPE ABUTMENT ;
    PORT
      LAYER met3 ;
      RECT 0.000 292.250 0.900 292.550 ;
    END
  END w0_wd_in[4]
  PIN w0_wd_in[5]
    DIRECTION INPUT ;
    USE SIGNAL ;
    SHAPE ABUTMENT ;
    PORT
      LAYER met3 ;
      RECT 0.000 297.690 0.900 297.990 ;
    END
  END w0_wd_in[5]
  PIN w0_wd_in[6]
    DIRECTION INPUT ;
    USE SIGNAL ;
    SHAPE ABUTMENT ;
    PORT
      LAYER met3 ;
      RECT 0.000 303.130 0.900 303.430 ;
    END
  END w0_wd_in[6]
  PIN w0_wd_in[7]
    DIRECTION INPUT ;
    USE SIGNAL ;
    SHAPE ABUTMENT ;
    PORT
      LAYER met3 ;
      RECT 0.000 308.570 0.900 308.870 ;
    END
  END w0_wd_in[7]
  PIN w0_wd_in[8]
    DIRECTION INPUT ;
    USE SIGNAL ;
    SHAPE ABUTMENT ;
    PORT
      LAYER met3 ;
      RECT 0.000 314.010 0.900 314.310 ;
    END
  END w0_wd_in[8]
  PIN w0_wd_in[9]
    DIRECTION INPUT ;
    USE SIGNAL ;
    SHAPE ABUTMENT ;
    PORT
      LAYER met3 ;
      RECT 0.000 319.450 0.900 319.750 ;
    END
  END w0_wd_in[9]
  PIN w0_wd_in[10]
    DIRECTION INPUT ;
    USE SIGNAL ;
    SHAPE ABUTMENT ;
    PORT
      LAYER met3 ;
      RECT 0.000 324.890 0.900 325.190 ;
    END
  END w0_wd_in[10]
  PIN w0_wd_in[11]
    DIRECTION INPUT ;
    USE SIGNAL ;
    SHAPE ABUTMENT ;
    PORT
      LAYER met3 ;
      RECT 0.000 330.330 0.900 330.630 ;
    END
  END w0_wd_in[11]
  PIN w0_wd_in[12]
    DIRECTION INPUT ;
    USE SIGNAL ;
    SHAPE ABUTMENT ;
    PORT
      LAYER met3 ;
      RECT 0.000 335.770 0.900 336.070 ;
    END
  END w0_wd_in[12]
  PIN w0_wd_in[13]
    DIRECTION INPUT ;
    USE SIGNAL ;
    SHAPE ABUTMENT ;
    PORT
      LAYER met3 ;
      RECT 0.000 341.210 0.900 341.510 ;
    END
  END w0_wd_in[13]
  PIN w0_wd_in[14]
    DIRECTION INPUT ;
    USE SIGNAL ;
    SHAPE ABUTMENT ;
    PORT
      LAYER met3 ;
      RECT 0.000 346.650 0.900 346.950 ;
    END
  END w0_wd_in[14]
  PIN w0_wd_in[15]
    DIRECTION INPUT ;
    USE SIGNAL ;
    SHAPE ABUTMENT ;
    PORT
      LAYER met3 ;
      RECT 0.000 352.090 0.900 352.390 ;
    END
  END w0_wd_in[15]
  PIN w0_wd_in[16]
    DIRECTION INPUT ;
    USE SIGNAL ;
    SHAPE ABUTMENT ;
    PORT
      LAYER met3 ;
      RECT 0.000 357.530 0.900 357.830 ;
    END
  END w0_wd_in[16]
  PIN w0_wd_in[17]
    DIRECTION INPUT ;
    USE SIGNAL ;
    SHAPE ABUTMENT ;
    PORT
      LAYER met3 ;
      RECT 0.000 362.970 0.900 363.270 ;
    END
  END w0_wd_in[17]
  PIN w0_wd_in[18]
    DIRECTION INPUT ;
    USE SIGNAL ;
    SHAPE ABUTMENT ;
    PORT
      LAYER met3 ;
      RECT 0.000 368.410 0.900 368.710 ;
    END
  END w0_wd_in[18]
  PIN w0_wd_in[19]
    DIRECTION INPUT ;
    USE SIGNAL ;
    SHAPE ABUTMENT ;
    PORT
      LAYER met3 ;
      RECT 0.000 373.850 0.900 374.150 ;
    END
  END w0_wd_in[19]
  PIN w0_wd_in[20]
    DIRECTION INPUT ;
    USE SIGNAL ;
    SHAPE ABUTMENT ;
    PORT
      LAYER met3 ;
      RECT 0.000 379.290 0.900 379.590 ;
    END
  END w0_wd_in[20]
  PIN w0_wd_in[21]
    DIRECTION INPUT ;
    USE SIGNAL ;
    SHAPE ABUTMENT ;
    PORT
      LAYER met3 ;
      RECT 0.000 384.730 0.900 385.030 ;
    END
  END w0_wd_in[21]
  PIN w0_wd_in[22]
    DIRECTION INPUT ;
    USE SIGNAL ;
    SHAPE ABUTMENT ;
    PORT
      LAYER met3 ;
      RECT 0.000 390.170 0.900 390.470 ;
    END
  END w0_wd_in[22]
  PIN w0_wd_in[23]
    DIRECTION INPUT ;
    USE SIGNAL ;
    SHAPE ABUTMENT ;
    PORT
      LAYER met3 ;
      RECT 0.000 395.610 0.900 395.910 ;
    END
  END w0_wd_in[23]
  PIN w0_wd_in[24]
    DIRECTION INPUT ;
    USE SIGNAL ;
    SHAPE ABUTMENT ;
    PORT
      LAYER met3 ;
      RECT 0.000 401.050 0.900 401.350 ;
    END
  END w0_wd_in[24]
  PIN w0_wd_in[25]
    DIRECTION INPUT ;
    USE SIGNAL ;
    SHAPE ABUTMENT ;
    PORT
      LAYER met3 ;
      RECT 0.000 406.490 0.900 406.790 ;
    END
  END w0_wd_in[25]
  PIN w0_wd_in[26]
    DIRECTION INPUT ;
    USE SIGNAL ;
    SHAPE ABUTMENT ;
    PORT
      LAYER met3 ;
      RECT 0.000 411.930 0.900 412.230 ;
    END
  END w0_wd_in[26]
  PIN w0_wd_in[27]
    DIRECTION INPUT ;
    USE SIGNAL ;
    SHAPE ABUTMENT ;
    PORT
      LAYER met3 ;
      RECT 0.000 417.370 0.900 417.670 ;
    END
  END w0_wd_in[27]
  PIN w0_wd_in[28]
    DIRECTION INPUT ;
    USE SIGNAL ;
    SHAPE ABUTMENT ;
    PORT
      LAYER met3 ;
      RECT 0.000 422.810 0.900 423.110 ;
    END
  END w0_wd_in[28]
  PIN w0_wd_in[29]
    DIRECTION INPUT ;
    USE SIGNAL ;
    SHAPE ABUTMENT ;
    PORT
      LAYER met3 ;
      RECT 0.000 428.250 0.900 428.550 ;
    END
  END w0_wd_in[29]
  PIN w0_wd_in[30]
    DIRECTION INPUT ;
    USE SIGNAL ;
    SHAPE ABUTMENT ;
    PORT
      LAYER met3 ;
      RECT 0.000 433.690 0.900 433.990 ;
    END
  END w0_wd_in[30]
  PIN w0_wd_in[31]
    DIRECTION INPUT ;
    USE SIGNAL ;
    SHAPE ABUTMENT ;
    PORT
      LAYER met3 ;
      RECT 0.000 439.130 0.900 439.430 ;
    END
  END w0_wd_in[31]
  PIN w0_wd_in[32]
    DIRECTION INPUT ;
    USE SIGNAL ;
    SHAPE ABUTMENT ;
    PORT
      LAYER met3 ;
      RECT 0.000 444.570 0.900 444.870 ;
    END
  END w0_wd_in[32]
  PIN w0_wd_in[33]
    DIRECTION INPUT ;
    USE SIGNAL ;
    SHAPE ABUTMENT ;
    PORT
      LAYER met3 ;
      RECT 0.000 450.010 0.900 450.310 ;
    END
  END w0_wd_in[33]
  PIN w0_wd_in[34]
    DIRECTION INPUT ;
    USE SIGNAL ;
    SHAPE ABUTMENT ;
    PORT
      LAYER met3 ;
      RECT 0.000 455.450 0.900 455.750 ;
    END
  END w0_wd_in[34]
  PIN w0_wd_in[35]
    DIRECTION INPUT ;
    USE SIGNAL ;
    SHAPE ABUTMENT ;
    PORT
      LAYER met3 ;
      RECT 0.000 460.890 0.900 461.190 ;
    END
  END w0_wd_in[35]
  PIN w0_wd_in[36]
    DIRECTION INPUT ;
    USE SIGNAL ;
    SHAPE ABUTMENT ;
    PORT
      LAYER met3 ;
      RECT 0.000 466.330 0.900 466.630 ;
    END
  END w0_wd_in[36]
  PIN w0_wd_in[37]
    DIRECTION INPUT ;
    USE SIGNAL ;
    SHAPE ABUTMENT ;
    PORT
      LAYER met3 ;
      RECT 0.000 471.770 0.900 472.070 ;
    END
  END w0_wd_in[37]
  PIN w0_wd_in[38]
    DIRECTION INPUT ;
    USE SIGNAL ;
    SHAPE ABUTMENT ;
    PORT
      LAYER met3 ;
      RECT 0.000 477.210 0.900 477.510 ;
    END
  END w0_wd_in[38]
  PIN w0_wd_in[39]
    DIRECTION INPUT ;
    USE SIGNAL ;
    SHAPE ABUTMENT ;
    PORT
      LAYER met3 ;
      RECT 0.000 482.650 0.900 482.950 ;
    END
  END w0_wd_in[39]
  PIN w0_wd_in[40]
    DIRECTION INPUT ;
    USE SIGNAL ;
    SHAPE ABUTMENT ;
    PORT
      LAYER met3 ;
      RECT 0.000 488.090 0.900 488.390 ;
    END
  END w0_wd_in[40]
  PIN w0_wd_in[41]
    DIRECTION INPUT ;
    USE SIGNAL ;
    SHAPE ABUTMENT ;
    PORT
      LAYER met3 ;
      RECT 0.000 493.530 0.900 493.830 ;
    END
  END w0_wd_in[41]
  PIN w0_wd_in[42]
    DIRECTION INPUT ;
    USE SIGNAL ;
    SHAPE ABUTMENT ;
    PORT
      LAYER met3 ;
      RECT 0.000 498.970 0.900 499.270 ;
    END
  END w0_wd_in[42]
  PIN w0_wd_in[43]
    DIRECTION INPUT ;
    USE SIGNAL ;
    SHAPE ABUTMENT ;
    PORT
      LAYER met3 ;
      RECT 0.000 504.410 0.900 504.710 ;
    END
  END w0_wd_in[43]
  PIN w0_wd_in[44]
    DIRECTION INPUT ;
    USE SIGNAL ;
    SHAPE ABUTMENT ;
    PORT
      LAYER met3 ;
      RECT 0.000 509.850 0.900 510.150 ;
    END
  END w0_wd_in[44]
  PIN w0_wd_in[45]
    DIRECTION INPUT ;
    USE SIGNAL ;
    SHAPE ABUTMENT ;
    PORT
      LAYER met3 ;
      RECT 0.000 515.290 0.900 515.590 ;
    END
  END w0_wd_in[45]
  PIN w0_wd_in[46]
    DIRECTION INPUT ;
    USE SIGNAL ;
    SHAPE ABUTMENT ;
    PORT
      LAYER met3 ;
      RECT 0.000 520.730 0.900 521.030 ;
    END
  END w0_wd_in[46]
  PIN w0_wd_in[47]
    DIRECTION INPUT ;
    USE SIGNAL ;
    SHAPE ABUTMENT ;
    PORT
      LAYER met3 ;
      RECT 0.000 526.170 0.900 526.470 ;
    END
  END w0_wd_in[47]
  PIN w0_wd_in[48]
    DIRECTION INPUT ;
    USE SIGNAL ;
    SHAPE ABUTMENT ;
    PORT
      LAYER met3 ;
      RECT 0.000 531.610 0.900 531.910 ;
    END
  END w0_wd_in[48]
  PIN w0_wd_in[49]
    DIRECTION INPUT ;
    USE SIGNAL ;
    SHAPE ABUTMENT ;
    PORT
      LAYER met3 ;
      RECT 351.000 265.050 351.900 265.350 ;
    END
  END w0_wd_in[49]
  PIN w0_wd_in[50]
    DIRECTION INPUT ;
    USE SIGNAL ;
    SHAPE ABUTMENT ;
    PORT
      LAYER met3 ;
      RECT 351.000 270.490 351.900 270.790 ;
    END
  END w0_wd_in[50]
  PIN w0_wd_in[51]
    DIRECTION INPUT ;
    USE SIGNAL ;
    SHAPE ABUTMENT ;
    PORT
      LAYER met3 ;
      RECT 351.000 275.930 351.900 276.230 ;
    END
  END w0_wd_in[51]
  PIN w0_wd_in[52]
    DIRECTION INPUT ;
    USE SIGNAL ;
    SHAPE ABUTMENT ;
    PORT
      LAYER met3 ;
      RECT 351.000 281.370 351.900 281.670 ;
    END
  END w0_wd_in[52]
  PIN w0_wd_in[53]
    DIRECTION INPUT ;
    USE SIGNAL ;
    SHAPE ABUTMENT ;
    PORT
      LAYER met3 ;
      RECT 351.000 286.810 351.900 287.110 ;
    END
  END w0_wd_in[53]
  PIN w0_wd_in[54]
    DIRECTION INPUT ;
    USE SIGNAL ;
    SHAPE ABUTMENT ;
    PORT
      LAYER met3 ;
      RECT 351.000 292.250 351.900 292.550 ;
    END
  END w0_wd_in[54]
  PIN w0_wd_in[55]
    DIRECTION INPUT ;
    USE SIGNAL ;
    SHAPE ABUTMENT ;
    PORT
      LAYER met3 ;
      RECT 351.000 297.690 351.900 297.990 ;
    END
  END w0_wd_in[55]
  PIN w0_wd_in[56]
    DIRECTION INPUT ;
    USE SIGNAL ;
    SHAPE ABUTMENT ;
    PORT
      LAYER met3 ;
      RECT 351.000 303.130 351.900 303.430 ;
    END
  END w0_wd_in[56]
  PIN w0_wd_in[57]
    DIRECTION INPUT ;
    USE SIGNAL ;
    SHAPE ABUTMENT ;
    PORT
      LAYER met3 ;
      RECT 351.000 308.570 351.900 308.870 ;
    END
  END w0_wd_in[57]
  PIN w0_wd_in[58]
    DIRECTION INPUT ;
    USE SIGNAL ;
    SHAPE ABUTMENT ;
    PORT
      LAYER met3 ;
      RECT 351.000 314.010 351.900 314.310 ;
    END
  END w0_wd_in[58]
  PIN w0_wd_in[59]
    DIRECTION INPUT ;
    USE SIGNAL ;
    SHAPE ABUTMENT ;
    PORT
      LAYER met3 ;
      RECT 351.000 319.450 351.900 319.750 ;
    END
  END w0_wd_in[59]
  PIN w0_wd_in[60]
    DIRECTION INPUT ;
    USE SIGNAL ;
    SHAPE ABUTMENT ;
    PORT
      LAYER met3 ;
      RECT 351.000 324.890 351.900 325.190 ;
    END
  END w0_wd_in[60]
  PIN w0_wd_in[61]
    DIRECTION INPUT ;
    USE SIGNAL ;
    SHAPE ABUTMENT ;
    PORT
      LAYER met3 ;
      RECT 351.000 330.330 351.900 330.630 ;
    END
  END w0_wd_in[61]
  PIN w0_wd_in[62]
    DIRECTION INPUT ;
    USE SIGNAL ;
    SHAPE ABUTMENT ;
    PORT
      LAYER met3 ;
      RECT 351.000 335.770 351.900 336.070 ;
    END
  END w0_wd_in[62]
  PIN w0_wd_in[63]
    DIRECTION INPUT ;
    USE SIGNAL ;
    SHAPE ABUTMENT ;
    PORT
      LAYER met3 ;
      RECT 351.000 341.210 351.900 341.510 ;
    END
  END w0_wd_in[63]
  PIN w0_wd_in[64]
    DIRECTION INPUT ;
    USE SIGNAL ;
    SHAPE ABUTMENT ;
    PORT
      LAYER met3 ;
      RECT 351.000 346.650 351.900 346.950 ;
    END
  END w0_wd_in[64]
  PIN w0_wd_in[65]
    DIRECTION INPUT ;
    USE SIGNAL ;
    SHAPE ABUTMENT ;
    PORT
      LAYER met3 ;
      RECT 351.000 352.090 351.900 352.390 ;
    END
  END w0_wd_in[65]
  PIN w0_wd_in[66]
    DIRECTION INPUT ;
    USE SIGNAL ;
    SHAPE ABUTMENT ;
    PORT
      LAYER met3 ;
      RECT 351.000 357.530 351.900 357.830 ;
    END
  END w0_wd_in[66]
  PIN w0_wd_in[67]
    DIRECTION INPUT ;
    USE SIGNAL ;
    SHAPE ABUTMENT ;
    PORT
      LAYER met3 ;
      RECT 351.000 362.970 351.900 363.270 ;
    END
  END w0_wd_in[67]
  PIN w0_wd_in[68]
    DIRECTION INPUT ;
    USE SIGNAL ;
    SHAPE ABUTMENT ;
    PORT
      LAYER met3 ;
      RECT 351.000 368.410 351.900 368.710 ;
    END
  END w0_wd_in[68]
  PIN w0_wd_in[69]
    DIRECTION INPUT ;
    USE SIGNAL ;
    SHAPE ABUTMENT ;
    PORT
      LAYER met3 ;
      RECT 351.000 373.850 351.900 374.150 ;
    END
  END w0_wd_in[69]
  PIN w0_wd_in[70]
    DIRECTION INPUT ;
    USE SIGNAL ;
    SHAPE ABUTMENT ;
    PORT
      LAYER met3 ;
      RECT 351.000 379.290 351.900 379.590 ;
    END
  END w0_wd_in[70]
  PIN w0_wd_in[71]
    DIRECTION INPUT ;
    USE SIGNAL ;
    SHAPE ABUTMENT ;
    PORT
      LAYER met3 ;
      RECT 351.000 384.730 351.900 385.030 ;
    END
  END w0_wd_in[71]
  PIN w0_wd_in[72]
    DIRECTION INPUT ;
    USE SIGNAL ;
    SHAPE ABUTMENT ;
    PORT
      LAYER met3 ;
      RECT 351.000 390.170 351.900 390.470 ;
    END
  END w0_wd_in[72]
  PIN w0_wd_in[73]
    DIRECTION INPUT ;
    USE SIGNAL ;
    SHAPE ABUTMENT ;
    PORT
      LAYER met3 ;
      RECT 351.000 395.610 351.900 395.910 ;
    END
  END w0_wd_in[73]
  PIN w0_wd_in[74]
    DIRECTION INPUT ;
    USE SIGNAL ;
    SHAPE ABUTMENT ;
    PORT
      LAYER met3 ;
      RECT 351.000 401.050 351.900 401.350 ;
    END
  END w0_wd_in[74]
  PIN w0_wd_in[75]
    DIRECTION INPUT ;
    USE SIGNAL ;
    SHAPE ABUTMENT ;
    PORT
      LAYER met3 ;
      RECT 351.000 406.490 351.900 406.790 ;
    END
  END w0_wd_in[75]
  PIN w0_wd_in[76]
    DIRECTION INPUT ;
    USE SIGNAL ;
    SHAPE ABUTMENT ;
    PORT
      LAYER met3 ;
      RECT 351.000 411.930 351.900 412.230 ;
    END
  END w0_wd_in[76]
  PIN w0_wd_in[77]
    DIRECTION INPUT ;
    USE SIGNAL ;
    SHAPE ABUTMENT ;
    PORT
      LAYER met3 ;
      RECT 351.000 417.370 351.900 417.670 ;
    END
  END w0_wd_in[77]
  PIN w0_wd_in[78]
    DIRECTION INPUT ;
    USE SIGNAL ;
    SHAPE ABUTMENT ;
    PORT
      LAYER met3 ;
      RECT 351.000 422.810 351.900 423.110 ;
    END
  END w0_wd_in[78]
  PIN w0_wd_in[79]
    DIRECTION INPUT ;
    USE SIGNAL ;
    SHAPE ABUTMENT ;
    PORT
      LAYER met3 ;
      RECT 351.000 428.250 351.900 428.550 ;
    END
  END w0_wd_in[79]
  PIN w0_wd_in[80]
    DIRECTION INPUT ;
    USE SIGNAL ;
    SHAPE ABUTMENT ;
    PORT
      LAYER met3 ;
      RECT 351.000 433.690 351.900 433.990 ;
    END
  END w0_wd_in[80]
  PIN w0_wd_in[81]
    DIRECTION INPUT ;
    USE SIGNAL ;
    SHAPE ABUTMENT ;
    PORT
      LAYER met3 ;
      RECT 351.000 439.130 351.900 439.430 ;
    END
  END w0_wd_in[81]
  PIN w0_wd_in[82]
    DIRECTION INPUT ;
    USE SIGNAL ;
    SHAPE ABUTMENT ;
    PORT
      LAYER met3 ;
      RECT 351.000 444.570 351.900 444.870 ;
    END
  END w0_wd_in[82]
  PIN w0_wd_in[83]
    DIRECTION INPUT ;
    USE SIGNAL ;
    SHAPE ABUTMENT ;
    PORT
      LAYER met3 ;
      RECT 351.000 450.010 351.900 450.310 ;
    END
  END w0_wd_in[83]
  PIN w0_wd_in[84]
    DIRECTION INPUT ;
    USE SIGNAL ;
    SHAPE ABUTMENT ;
    PORT
      LAYER met3 ;
      RECT 351.000 455.450 351.900 455.750 ;
    END
  END w0_wd_in[84]
  PIN w0_wd_in[85]
    DIRECTION INPUT ;
    USE SIGNAL ;
    SHAPE ABUTMENT ;
    PORT
      LAYER met3 ;
      RECT 351.000 460.890 351.900 461.190 ;
    END
  END w0_wd_in[85]
  PIN w0_wd_in[86]
    DIRECTION INPUT ;
    USE SIGNAL ;
    SHAPE ABUTMENT ;
    PORT
      LAYER met3 ;
      RECT 351.000 466.330 351.900 466.630 ;
    END
  END w0_wd_in[86]
  PIN w0_wd_in[87]
    DIRECTION INPUT ;
    USE SIGNAL ;
    SHAPE ABUTMENT ;
    PORT
      LAYER met3 ;
      RECT 351.000 471.770 351.900 472.070 ;
    END
  END w0_wd_in[87]
  PIN w0_wd_in[88]
    DIRECTION INPUT ;
    USE SIGNAL ;
    SHAPE ABUTMENT ;
    PORT
      LAYER met3 ;
      RECT 351.000 477.210 351.900 477.510 ;
    END
  END w0_wd_in[88]
  PIN w0_wd_in[89]
    DIRECTION INPUT ;
    USE SIGNAL ;
    SHAPE ABUTMENT ;
    PORT
      LAYER met3 ;
      RECT 351.000 482.650 351.900 482.950 ;
    END
  END w0_wd_in[89]
  PIN w0_wd_in[90]
    DIRECTION INPUT ;
    USE SIGNAL ;
    SHAPE ABUTMENT ;
    PORT
      LAYER met3 ;
      RECT 351.000 488.090 351.900 488.390 ;
    END
  END w0_wd_in[90]
  PIN w0_wd_in[91]
    DIRECTION INPUT ;
    USE SIGNAL ;
    SHAPE ABUTMENT ;
    PORT
      LAYER met3 ;
      RECT 351.000 493.530 351.900 493.830 ;
    END
  END w0_wd_in[91]
  PIN w0_wd_in[92]
    DIRECTION INPUT ;
    USE SIGNAL ;
    SHAPE ABUTMENT ;
    PORT
      LAYER met3 ;
      RECT 351.000 498.970 351.900 499.270 ;
    END
  END w0_wd_in[92]
  PIN w0_wd_in[93]
    DIRECTION INPUT ;
    USE SIGNAL ;
    SHAPE ABUTMENT ;
    PORT
      LAYER met3 ;
      RECT 351.000 504.410 351.900 504.710 ;
    END
  END w0_wd_in[93]
  PIN w0_wd_in[94]
    DIRECTION INPUT ;
    USE SIGNAL ;
    SHAPE ABUTMENT ;
    PORT
      LAYER met3 ;
      RECT 351.000 509.850 351.900 510.150 ;
    END
  END w0_wd_in[94]
  PIN w0_wd_in[95]
    DIRECTION INPUT ;
    USE SIGNAL ;
    SHAPE ABUTMENT ;
    PORT
      LAYER met3 ;
      RECT 351.000 515.290 351.900 515.590 ;
    END
  END w0_wd_in[95]
  PIN w0_wd_in[96]
    DIRECTION INPUT ;
    USE SIGNAL ;
    SHAPE ABUTMENT ;
    PORT
      LAYER met3 ;
      RECT 351.000 520.730 351.900 521.030 ;
    END
  END w0_wd_in[96]
  PIN w0_wd_in[97]
    DIRECTION OUTPUT ;
    USE SIGNAL ;
    SHAPE ABUTMENT ;
    PORT
      LAYER met2 ;
      RECT 2.690 0.000 2.830 0.420 ;
    END
  END w0_wd_in[97]
  PIN w0_wd_in[98]
    DIRECTION OUTPUT ;
    USE SIGNAL ;
    SHAPE ABUTMENT ;
    PORT
      LAYER met2 ;
      RECT 4.070 0.000 4.210 0.420 ;
    END
  END w0_wd_in[98]
  PIN w0_wd_in[99]
    DIRECTION OUTPUT ;
    USE SIGNAL ;
    SHAPE ABUTMENT ;
    PORT
      LAYER met2 ;
      RECT 5.450 0.000 5.590 0.420 ;
    END
  END w0_wd_in[99]
  PIN w0_wd_in[100]
    DIRECTION OUTPUT ;
    USE SIGNAL ;
    SHAPE ABUTMENT ;
    PORT
      LAYER met2 ;
      RECT 6.830 0.000 6.970 0.420 ;
    END
  END w0_wd_in[100]
  PIN w0_wd_in[101]
    DIRECTION OUTPUT ;
    USE SIGNAL ;
    SHAPE ABUTMENT ;
    PORT
      LAYER met2 ;
      RECT 8.210 0.000 8.350 0.420 ;
    END
  END w0_wd_in[101]
  PIN w0_wd_in[102]
    DIRECTION OUTPUT ;
    USE SIGNAL ;
    SHAPE ABUTMENT ;
    PORT
      LAYER met2 ;
      RECT 9.590 0.000 9.730 0.420 ;
    END
  END w0_wd_in[102]
  PIN w0_wd_in[103]
    DIRECTION OUTPUT ;
    USE SIGNAL ;
    SHAPE ABUTMENT ;
    PORT
      LAYER met2 ;
      RECT 10.970 0.000 11.110 0.420 ;
    END
  END w0_wd_in[103]
  PIN w0_wd_in[104]
    DIRECTION OUTPUT ;
    USE SIGNAL ;
    SHAPE ABUTMENT ;
    PORT
      LAYER met2 ;
      RECT 12.350 0.000 12.490 0.420 ;
    END
  END w0_wd_in[104]
  PIN w0_wd_in[105]
    DIRECTION OUTPUT ;
    USE SIGNAL ;
    SHAPE ABUTMENT ;
    PORT
      LAYER met2 ;
      RECT 13.730 0.000 13.870 0.420 ;
    END
  END w0_wd_in[105]
  PIN w0_wd_in[106]
    DIRECTION OUTPUT ;
    USE SIGNAL ;
    SHAPE ABUTMENT ;
    PORT
      LAYER met2 ;
      RECT 15.110 0.000 15.250 0.420 ;
    END
  END w0_wd_in[106]
  PIN w0_wd_in[107]
    DIRECTION OUTPUT ;
    USE SIGNAL ;
    SHAPE ABUTMENT ;
    PORT
      LAYER met2 ;
      RECT 16.490 0.000 16.630 0.420 ;
    END
  END w0_wd_in[107]
  PIN w0_wd_in[108]
    DIRECTION OUTPUT ;
    USE SIGNAL ;
    SHAPE ABUTMENT ;
    PORT
      LAYER met2 ;
      RECT 17.870 0.000 18.010 0.420 ;
    END
  END w0_wd_in[108]
  PIN w0_wd_in[109]
    DIRECTION OUTPUT ;
    USE SIGNAL ;
    SHAPE ABUTMENT ;
    PORT
      LAYER met2 ;
      RECT 19.250 0.000 19.390 0.420 ;
    END
  END w0_wd_in[109]
  PIN w0_wd_in[110]
    DIRECTION OUTPUT ;
    USE SIGNAL ;
    SHAPE ABUTMENT ;
    PORT
      LAYER met2 ;
      RECT 20.630 0.000 20.770 0.420 ;
    END
  END w0_wd_in[110]
  PIN w0_wd_in[111]
    DIRECTION OUTPUT ;
    USE SIGNAL ;
    SHAPE ABUTMENT ;
    PORT
      LAYER met2 ;
      RECT 22.010 0.000 22.150 0.420 ;
    END
  END w0_wd_in[111]
  PIN w0_wd_in[112]
    DIRECTION OUTPUT ;
    USE SIGNAL ;
    SHAPE ABUTMENT ;
    PORT
      LAYER met2 ;
      RECT 23.390 0.000 23.530 0.420 ;
    END
  END w0_wd_in[112]
  PIN w0_wd_in[113]
    DIRECTION OUTPUT ;
    USE SIGNAL ;
    SHAPE ABUTMENT ;
    PORT
      LAYER met2 ;
      RECT 24.770 0.000 24.910 0.420 ;
    END
  END w0_wd_in[113]
  PIN w0_wd_in[114]
    DIRECTION OUTPUT ;
    USE SIGNAL ;
    SHAPE ABUTMENT ;
    PORT
      LAYER met2 ;
      RECT 26.150 0.000 26.290 0.420 ;
    END
  END w0_wd_in[114]
  PIN w0_wd_in[115]
    DIRECTION OUTPUT ;
    USE SIGNAL ;
    SHAPE ABUTMENT ;
    PORT
      LAYER met2 ;
      RECT 27.530 0.000 27.670 0.420 ;
    END
  END w0_wd_in[115]
  PIN w0_wd_in[116]
    DIRECTION OUTPUT ;
    USE SIGNAL ;
    SHAPE ABUTMENT ;
    PORT
      LAYER met2 ;
      RECT 28.910 0.000 29.050 0.420 ;
    END
  END w0_wd_in[116]
  PIN w0_wd_in[117]
    DIRECTION OUTPUT ;
    USE SIGNAL ;
    SHAPE ABUTMENT ;
    PORT
      LAYER met2 ;
      RECT 30.290 0.000 30.430 0.420 ;
    END
  END w0_wd_in[117]
  PIN w0_wd_in[118]
    DIRECTION OUTPUT ;
    USE SIGNAL ;
    SHAPE ABUTMENT ;
    PORT
      LAYER met2 ;
      RECT 31.670 0.000 31.810 0.420 ;
    END
  END w0_wd_in[118]
  PIN w0_wd_in[119]
    DIRECTION OUTPUT ;
    USE SIGNAL ;
    SHAPE ABUTMENT ;
    PORT
      LAYER met2 ;
      RECT 33.050 0.000 33.190 0.420 ;
    END
  END w0_wd_in[119]
  PIN w0_wd_in[120]
    DIRECTION OUTPUT ;
    USE SIGNAL ;
    SHAPE ABUTMENT ;
    PORT
      LAYER met2 ;
      RECT 34.430 0.000 34.570 0.420 ;
    END
  END w0_wd_in[120]
  PIN w0_wd_in[121]
    DIRECTION OUTPUT ;
    USE SIGNAL ;
    SHAPE ABUTMENT ;
    PORT
      LAYER met2 ;
      RECT 35.810 0.000 35.950 0.420 ;
    END
  END w0_wd_in[121]
  PIN w0_wd_in[122]
    DIRECTION OUTPUT ;
    USE SIGNAL ;
    SHAPE ABUTMENT ;
    PORT
      LAYER met2 ;
      RECT 37.190 0.000 37.330 0.420 ;
    END
  END w0_wd_in[122]
  PIN w0_wd_in[123]
    DIRECTION OUTPUT ;
    USE SIGNAL ;
    SHAPE ABUTMENT ;
    PORT
      LAYER met2 ;
      RECT 38.570 0.000 38.710 0.420 ;
    END
  END w0_wd_in[123]
  PIN w0_wd_in[124]
    DIRECTION OUTPUT ;
    USE SIGNAL ;
    SHAPE ABUTMENT ;
    PORT
      LAYER met2 ;
      RECT 39.950 0.000 40.090 0.420 ;
    END
  END w0_wd_in[124]
  PIN w0_wd_in[125]
    DIRECTION OUTPUT ;
    USE SIGNAL ;
    SHAPE ABUTMENT ;
    PORT
      LAYER met2 ;
      RECT 41.330 0.000 41.470 0.420 ;
    END
  END w0_wd_in[125]
  PIN w0_wd_in[126]
    DIRECTION OUTPUT ;
    USE SIGNAL ;
    SHAPE ABUTMENT ;
    PORT
      LAYER met2 ;
      RECT 42.710 0.000 42.850 0.420 ;
    END
  END w0_wd_in[126]
  PIN w0_wd_in[127]
    DIRECTION OUTPUT ;
    USE SIGNAL ;
    SHAPE ABUTMENT ;
    PORT
      LAYER met2 ;
      RECT 44.090 0.000 44.230 0.420 ;
    END
  END w0_wd_in[127]
  PIN w0_wd_in[128]
    DIRECTION OUTPUT ;
    USE SIGNAL ;
    SHAPE ABUTMENT ;
    PORT
      LAYER met2 ;
      RECT 45.470 0.000 45.610 0.420 ;
    END
  END w0_wd_in[128]
  PIN w0_wd_in[129]
    DIRECTION OUTPUT ;
    USE SIGNAL ;
    SHAPE ABUTMENT ;
    PORT
      LAYER met2 ;
      RECT 46.850 0.000 46.990 0.420 ;
    END
  END w0_wd_in[129]
  PIN w0_wd_in[130]
    DIRECTION OUTPUT ;
    USE SIGNAL ;
    SHAPE ABUTMENT ;
    PORT
      LAYER met2 ;
      RECT 48.230 0.000 48.370 0.420 ;
    END
  END w0_wd_in[130]
  PIN w0_wd_in[131]
    DIRECTION OUTPUT ;
    USE SIGNAL ;
    SHAPE ABUTMENT ;
    PORT
      LAYER met2 ;
      RECT 49.610 0.000 49.750 0.420 ;
    END
  END w0_wd_in[131]
  PIN w0_wd_in[132]
    DIRECTION OUTPUT ;
    USE SIGNAL ;
    SHAPE ABUTMENT ;
    PORT
      LAYER met2 ;
      RECT 50.990 0.000 51.130 0.420 ;
    END
  END w0_wd_in[132]
  PIN w0_wd_in[133]
    DIRECTION OUTPUT ;
    USE SIGNAL ;
    SHAPE ABUTMENT ;
    PORT
      LAYER met2 ;
      RECT 52.370 0.000 52.510 0.420 ;
    END
  END w0_wd_in[133]
  PIN w0_wd_in[134]
    DIRECTION OUTPUT ;
    USE SIGNAL ;
    SHAPE ABUTMENT ;
    PORT
      LAYER met2 ;
      RECT 53.750 0.000 53.890 0.420 ;
    END
  END w0_wd_in[134]
  PIN w0_wd_in[135]
    DIRECTION OUTPUT ;
    USE SIGNAL ;
    SHAPE ABUTMENT ;
    PORT
      LAYER met2 ;
      RECT 55.130 0.000 55.270 0.420 ;
    END
  END w0_wd_in[135]
  PIN w0_wd_in[136]
    DIRECTION OUTPUT ;
    USE SIGNAL ;
    SHAPE ABUTMENT ;
    PORT
      LAYER met2 ;
      RECT 56.510 0.000 56.650 0.420 ;
    END
  END w0_wd_in[136]
  PIN w0_wd_in[137]
    DIRECTION OUTPUT ;
    USE SIGNAL ;
    SHAPE ABUTMENT ;
    PORT
      LAYER met2 ;
      RECT 57.890 0.000 58.030 0.420 ;
    END
  END w0_wd_in[137]
  PIN w0_wd_in[138]
    DIRECTION OUTPUT ;
    USE SIGNAL ;
    SHAPE ABUTMENT ;
    PORT
      LAYER met2 ;
      RECT 59.270 0.000 59.410 0.420 ;
    END
  END w0_wd_in[138]
  PIN w0_wd_in[139]
    DIRECTION OUTPUT ;
    USE SIGNAL ;
    SHAPE ABUTMENT ;
    PORT
      LAYER met2 ;
      RECT 60.650 0.000 60.790 0.420 ;
    END
  END w0_wd_in[139]
  PIN w0_wd_in[140]
    DIRECTION OUTPUT ;
    USE SIGNAL ;
    SHAPE ABUTMENT ;
    PORT
      LAYER met2 ;
      RECT 62.030 0.000 62.170 0.420 ;
    END
  END w0_wd_in[140]
  PIN w0_wd_in[141]
    DIRECTION OUTPUT ;
    USE SIGNAL ;
    SHAPE ABUTMENT ;
    PORT
      LAYER met2 ;
      RECT 63.410 0.000 63.550 0.420 ;
    END
  END w0_wd_in[141]
  PIN w0_wd_in[142]
    DIRECTION OUTPUT ;
    USE SIGNAL ;
    SHAPE ABUTMENT ;
    PORT
      LAYER met2 ;
      RECT 64.790 0.000 64.930 0.420 ;
    END
  END w0_wd_in[142]
  PIN w0_wd_in[143]
    DIRECTION OUTPUT ;
    USE SIGNAL ;
    SHAPE ABUTMENT ;
    PORT
      LAYER met2 ;
      RECT 66.170 0.000 66.310 0.420 ;
    END
  END w0_wd_in[143]
  PIN w0_wd_in[144]
    DIRECTION OUTPUT ;
    USE SIGNAL ;
    SHAPE ABUTMENT ;
    PORT
      LAYER met2 ;
      RECT 67.550 0.000 67.690 0.420 ;
    END
  END w0_wd_in[144]
  PIN w0_wd_in[145]
    DIRECTION OUTPUT ;
    USE SIGNAL ;
    SHAPE ABUTMENT ;
    PORT
      LAYER met2 ;
      RECT 68.930 0.000 69.070 0.420 ;
    END
  END w0_wd_in[145]
  PIN w0_wd_in[146]
    DIRECTION OUTPUT ;
    USE SIGNAL ;
    SHAPE ABUTMENT ;
    PORT
      LAYER met2 ;
      RECT 70.310 0.000 70.450 0.420 ;
    END
  END w0_wd_in[146]
  PIN w0_wd_in[147]
    DIRECTION OUTPUT ;
    USE SIGNAL ;
    SHAPE ABUTMENT ;
    PORT
      LAYER met2 ;
      RECT 71.690 0.000 71.830 0.420 ;
    END
  END w0_wd_in[147]
  PIN w0_wd_in[148]
    DIRECTION OUTPUT ;
    USE SIGNAL ;
    SHAPE ABUTMENT ;
    PORT
      LAYER met2 ;
      RECT 73.070 0.000 73.210 0.420 ;
    END
  END w0_wd_in[148]
  PIN w0_wd_in[149]
    DIRECTION OUTPUT ;
    USE SIGNAL ;
    SHAPE ABUTMENT ;
    PORT
      LAYER met2 ;
      RECT 74.450 0.000 74.590 0.420 ;
    END
  END w0_wd_in[149]
  PIN w0_wd_in[150]
    DIRECTION OUTPUT ;
    USE SIGNAL ;
    SHAPE ABUTMENT ;
    PORT
      LAYER met2 ;
      RECT 75.830 0.000 75.970 0.420 ;
    END
  END w0_wd_in[150]
  PIN w0_wd_in[151]
    DIRECTION OUTPUT ;
    USE SIGNAL ;
    SHAPE ABUTMENT ;
    PORT
      LAYER met2 ;
      RECT 77.210 0.000 77.350 0.420 ;
    END
  END w0_wd_in[151]
  PIN w0_wd_in[152]
    DIRECTION OUTPUT ;
    USE SIGNAL ;
    SHAPE ABUTMENT ;
    PORT
      LAYER met2 ;
      RECT 78.590 0.000 78.730 0.420 ;
    END
  END w0_wd_in[152]
  PIN w0_wd_in[153]
    DIRECTION OUTPUT ;
    USE SIGNAL ;
    SHAPE ABUTMENT ;
    PORT
      LAYER met2 ;
      RECT 79.970 0.000 80.110 0.420 ;
    END
  END w0_wd_in[153]
  PIN w0_wd_in[154]
    DIRECTION OUTPUT ;
    USE SIGNAL ;
    SHAPE ABUTMENT ;
    PORT
      LAYER met2 ;
      RECT 81.350 0.000 81.490 0.420 ;
    END
  END w0_wd_in[154]
  PIN w0_wd_in[155]
    DIRECTION OUTPUT ;
    USE SIGNAL ;
    SHAPE ABUTMENT ;
    PORT
      LAYER met2 ;
      RECT 82.730 0.000 82.870 0.420 ;
    END
  END w0_wd_in[155]
  PIN w0_wd_in[156]
    DIRECTION OUTPUT ;
    USE SIGNAL ;
    SHAPE ABUTMENT ;
    PORT
      LAYER met2 ;
      RECT 84.110 0.000 84.250 0.420 ;
    END
  END w0_wd_in[156]
  PIN w0_wd_in[157]
    DIRECTION OUTPUT ;
    USE SIGNAL ;
    SHAPE ABUTMENT ;
    PORT
      LAYER met2 ;
      RECT 85.490 0.000 85.630 0.420 ;
    END
  END w0_wd_in[157]
  PIN w0_wd_in[158]
    DIRECTION OUTPUT ;
    USE SIGNAL ;
    SHAPE ABUTMENT ;
    PORT
      LAYER met2 ;
      RECT 86.870 0.000 87.010 0.420 ;
    END
  END w0_wd_in[158]
  PIN w0_wd_in[159]
    DIRECTION OUTPUT ;
    USE SIGNAL ;
    SHAPE ABUTMENT ;
    PORT
      LAYER met2 ;
      RECT 88.250 0.000 88.390 0.420 ;
    END
  END w0_wd_in[159]
  PIN w0_wd_in[160]
    DIRECTION OUTPUT ;
    USE SIGNAL ;
    SHAPE ABUTMENT ;
    PORT
      LAYER met2 ;
      RECT 89.630 0.000 89.770 0.420 ;
    END
  END w0_wd_in[160]
  PIN w0_wd_in[161]
    DIRECTION OUTPUT ;
    USE SIGNAL ;
    SHAPE ABUTMENT ;
    PORT
      LAYER met2 ;
      RECT 91.010 0.000 91.150 0.420 ;
    END
  END w0_wd_in[161]
  PIN w0_wd_in[162]
    DIRECTION OUTPUT ;
    USE SIGNAL ;
    SHAPE ABUTMENT ;
    PORT
      LAYER met2 ;
      RECT 92.390 0.000 92.530 0.420 ;
    END
  END w0_wd_in[162]
  PIN w0_wd_in[163]
    DIRECTION OUTPUT ;
    USE SIGNAL ;
    SHAPE ABUTMENT ;
    PORT
      LAYER met2 ;
      RECT 93.770 0.000 93.910 0.420 ;
    END
  END w0_wd_in[163]
  PIN w0_wd_in[164]
    DIRECTION OUTPUT ;
    USE SIGNAL ;
    SHAPE ABUTMENT ;
    PORT
      LAYER met2 ;
      RECT 95.150 0.000 95.290 0.420 ;
    END
  END w0_wd_in[164]
  PIN w0_wd_in[165]
    DIRECTION OUTPUT ;
    USE SIGNAL ;
    SHAPE ABUTMENT ;
    PORT
      LAYER met2 ;
      RECT 96.530 0.000 96.670 0.420 ;
    END
  END w0_wd_in[165]
  PIN w0_wd_in[166]
    DIRECTION OUTPUT ;
    USE SIGNAL ;
    SHAPE ABUTMENT ;
    PORT
      LAYER met2 ;
      RECT 97.910 0.000 98.050 0.420 ;
    END
  END w0_wd_in[166]
  PIN w0_wd_in[167]
    DIRECTION OUTPUT ;
    USE SIGNAL ;
    SHAPE ABUTMENT ;
    PORT
      LAYER met2 ;
      RECT 99.290 0.000 99.430 0.420 ;
    END
  END w0_wd_in[167]
  PIN w0_wd_in[168]
    DIRECTION OUTPUT ;
    USE SIGNAL ;
    SHAPE ABUTMENT ;
    PORT
      LAYER met2 ;
      RECT 100.670 0.000 100.810 0.420 ;
    END
  END w0_wd_in[168]
  PIN w0_wd_in[169]
    DIRECTION OUTPUT ;
    USE SIGNAL ;
    SHAPE ABUTMENT ;
    PORT
      LAYER met2 ;
      RECT 102.050 0.000 102.190 0.420 ;
    END
  END w0_wd_in[169]
  PIN w0_wd_in[170]
    DIRECTION OUTPUT ;
    USE SIGNAL ;
    SHAPE ABUTMENT ;
    PORT
      LAYER met2 ;
      RECT 103.430 0.000 103.570 0.420 ;
    END
  END w0_wd_in[170]
  PIN w0_wd_in[171]
    DIRECTION OUTPUT ;
    USE SIGNAL ;
    SHAPE ABUTMENT ;
    PORT
      LAYER met2 ;
      RECT 104.810 0.000 104.950 0.420 ;
    END
  END w0_wd_in[171]
  PIN w0_wd_in[172]
    DIRECTION OUTPUT ;
    USE SIGNAL ;
    SHAPE ABUTMENT ;
    PORT
      LAYER met2 ;
      RECT 106.190 0.000 106.330 0.420 ;
    END
  END w0_wd_in[172]
  PIN w0_wd_in[173]
    DIRECTION OUTPUT ;
    USE SIGNAL ;
    SHAPE ABUTMENT ;
    PORT
      LAYER met2 ;
      RECT 107.570 0.000 107.710 0.420 ;
    END
  END w0_wd_in[173]
  PIN w0_wd_in[174]
    DIRECTION OUTPUT ;
    USE SIGNAL ;
    SHAPE ABUTMENT ;
    PORT
      LAYER met2 ;
      RECT 108.950 0.000 109.090 0.420 ;
    END
  END w0_wd_in[174]
  PIN w0_wd_in[175]
    DIRECTION OUTPUT ;
    USE SIGNAL ;
    SHAPE ABUTMENT ;
    PORT
      LAYER met2 ;
      RECT 110.330 0.000 110.470 0.420 ;
    END
  END w0_wd_in[175]
  PIN w0_wd_in[176]
    DIRECTION OUTPUT ;
    USE SIGNAL ;
    SHAPE ABUTMENT ;
    PORT
      LAYER met2 ;
      RECT 111.710 0.000 111.850 0.420 ;
    END
  END w0_wd_in[176]
  PIN w0_wd_in[177]
    DIRECTION OUTPUT ;
    USE SIGNAL ;
    SHAPE ABUTMENT ;
    PORT
      LAYER met2 ;
      RECT 113.090 0.000 113.230 0.420 ;
    END
  END w0_wd_in[177]
  PIN w0_wd_in[178]
    DIRECTION OUTPUT ;
    USE SIGNAL ;
    SHAPE ABUTMENT ;
    PORT
      LAYER met2 ;
      RECT 114.470 0.000 114.610 0.420 ;
    END
  END w0_wd_in[178]
  PIN w0_wd_in[179]
    DIRECTION OUTPUT ;
    USE SIGNAL ;
    SHAPE ABUTMENT ;
    PORT
      LAYER met2 ;
      RECT 115.850 0.000 115.990 0.420 ;
    END
  END w0_wd_in[179]
  PIN w0_wd_in[180]
    DIRECTION OUTPUT ;
    USE SIGNAL ;
    SHAPE ABUTMENT ;
    PORT
      LAYER met2 ;
      RECT 117.230 0.000 117.370 0.420 ;
    END
  END w0_wd_in[180]
  PIN w0_wd_in[181]
    DIRECTION OUTPUT ;
    USE SIGNAL ;
    SHAPE ABUTMENT ;
    PORT
      LAYER met2 ;
      RECT 118.610 0.000 118.750 0.420 ;
    END
  END w0_wd_in[181]
  PIN w0_wd_in[182]
    DIRECTION OUTPUT ;
    USE SIGNAL ;
    SHAPE ABUTMENT ;
    PORT
      LAYER met2 ;
      RECT 119.990 0.000 120.130 0.420 ;
    END
  END w0_wd_in[182]
  PIN w0_wd_in[183]
    DIRECTION OUTPUT ;
    USE SIGNAL ;
    SHAPE ABUTMENT ;
    PORT
      LAYER met2 ;
      RECT 121.370 0.000 121.510 0.420 ;
    END
  END w0_wd_in[183]
  PIN w0_wd_in[184]
    DIRECTION OUTPUT ;
    USE SIGNAL ;
    SHAPE ABUTMENT ;
    PORT
      LAYER met2 ;
      RECT 122.750 0.000 122.890 0.420 ;
    END
  END w0_wd_in[184]
  PIN w0_wd_in[185]
    DIRECTION OUTPUT ;
    USE SIGNAL ;
    SHAPE ABUTMENT ;
    PORT
      LAYER met2 ;
      RECT 124.130 0.000 124.270 0.420 ;
    END
  END w0_wd_in[185]
  PIN w0_wd_in[186]
    DIRECTION OUTPUT ;
    USE SIGNAL ;
    SHAPE ABUTMENT ;
    PORT
      LAYER met2 ;
      RECT 125.510 0.000 125.650 0.420 ;
    END
  END w0_wd_in[186]
  PIN w0_wd_in[187]
    DIRECTION OUTPUT ;
    USE SIGNAL ;
    SHAPE ABUTMENT ;
    PORT
      LAYER met2 ;
      RECT 126.890 0.000 127.030 0.420 ;
    END
  END w0_wd_in[187]
  PIN w0_wd_in[188]
    DIRECTION OUTPUT ;
    USE SIGNAL ;
    SHAPE ABUTMENT ;
    PORT
      LAYER met2 ;
      RECT 128.270 0.000 128.410 0.420 ;
    END
  END w0_wd_in[188]
  PIN w0_wd_in[189]
    DIRECTION OUTPUT ;
    USE SIGNAL ;
    SHAPE ABUTMENT ;
    PORT
      LAYER met2 ;
      RECT 129.650 0.000 129.790 0.420 ;
    END
  END w0_wd_in[189]
  PIN w0_wd_in[190]
    DIRECTION OUTPUT ;
    USE SIGNAL ;
    SHAPE ABUTMENT ;
    PORT
      LAYER met2 ;
      RECT 131.030 0.000 131.170 0.420 ;
    END
  END w0_wd_in[190]
  PIN w0_wd_in[191]
    DIRECTION OUTPUT ;
    USE SIGNAL ;
    SHAPE ABUTMENT ;
    PORT
      LAYER met2 ;
      RECT 132.410 0.000 132.550 0.420 ;
    END
  END w0_wd_in[191]
  PIN w0_wd_in[192]
    DIRECTION OUTPUT ;
    USE SIGNAL ;
    SHAPE ABUTMENT ;
    PORT
      LAYER met2 ;
      RECT 133.790 0.000 133.930 0.420 ;
    END
  END w0_wd_in[192]
  PIN r0_rd_out[0]
    DIRECTION OUTPUT ;
    USE SIGNAL ;
    SHAPE ABUTMENT ;
    PORT
      LAYER met2 ;
      RECT 135.170 0.000 135.310 0.420 ;
    END
  END r0_rd_out[0]
  PIN r0_rd_out[1]
    DIRECTION OUTPUT ;
    USE SIGNAL ;
    SHAPE ABUTMENT ;
    PORT
      LAYER met2 ;
      RECT 136.550 0.000 136.690 0.420 ;
    END
  END r0_rd_out[1]
  PIN r0_rd_out[2]
    DIRECTION OUTPUT ;
    USE SIGNAL ;
    SHAPE ABUTMENT ;
    PORT
      LAYER met2 ;
      RECT 137.930 0.000 138.070 0.420 ;
    END
  END r0_rd_out[2]
  PIN r0_rd_out[3]
    DIRECTION OUTPUT ;
    USE SIGNAL ;
    SHAPE ABUTMENT ;
    PORT
      LAYER met2 ;
      RECT 139.310 0.000 139.450 0.420 ;
    END
  END r0_rd_out[3]
  PIN r0_rd_out[4]
    DIRECTION OUTPUT ;
    USE SIGNAL ;
    SHAPE ABUTMENT ;
    PORT
      LAYER met2 ;
      RECT 140.690 0.000 140.830 0.420 ;
    END
  END r0_rd_out[4]
  PIN r0_rd_out[5]
    DIRECTION OUTPUT ;
    USE SIGNAL ;
    SHAPE ABUTMENT ;
    PORT
      LAYER met2 ;
      RECT 142.070 0.000 142.210 0.420 ;
    END
  END r0_rd_out[5]
  PIN r0_rd_out[6]
    DIRECTION OUTPUT ;
    USE SIGNAL ;
    SHAPE ABUTMENT ;
    PORT
      LAYER met2 ;
      RECT 143.450 0.000 143.590 0.420 ;
    END
  END r0_rd_out[6]
  PIN r0_rd_out[7]
    DIRECTION OUTPUT ;
    USE SIGNAL ;
    SHAPE ABUTMENT ;
    PORT
      LAYER met2 ;
      RECT 144.830 0.000 144.970 0.420 ;
    END
  END r0_rd_out[7]
  PIN r0_rd_out[8]
    DIRECTION OUTPUT ;
    USE SIGNAL ;
    SHAPE ABUTMENT ;
    PORT
      LAYER met2 ;
      RECT 146.210 0.000 146.350 0.420 ;
    END
  END r0_rd_out[8]
  PIN r0_rd_out[9]
    DIRECTION OUTPUT ;
    USE SIGNAL ;
    SHAPE ABUTMENT ;
    PORT
      LAYER met2 ;
      RECT 147.590 0.000 147.730 0.420 ;
    END
  END r0_rd_out[9]
  PIN r0_rd_out[10]
    DIRECTION OUTPUT ;
    USE SIGNAL ;
    SHAPE ABUTMENT ;
    PORT
      LAYER met2 ;
      RECT 148.970 0.000 149.110 0.420 ;
    END
  END r0_rd_out[10]
  PIN r0_rd_out[11]
    DIRECTION OUTPUT ;
    USE SIGNAL ;
    SHAPE ABUTMENT ;
    PORT
      LAYER met2 ;
      RECT 150.350 0.000 150.490 0.420 ;
    END
  END r0_rd_out[11]
  PIN r0_rd_out[12]
    DIRECTION OUTPUT ;
    USE SIGNAL ;
    SHAPE ABUTMENT ;
    PORT
      LAYER met2 ;
      RECT 151.730 0.000 151.870 0.420 ;
    END
  END r0_rd_out[12]
  PIN r0_rd_out[13]
    DIRECTION OUTPUT ;
    USE SIGNAL ;
    SHAPE ABUTMENT ;
    PORT
      LAYER met2 ;
      RECT 153.110 0.000 153.250 0.420 ;
    END
  END r0_rd_out[13]
  PIN r0_rd_out[14]
    DIRECTION OUTPUT ;
    USE SIGNAL ;
    SHAPE ABUTMENT ;
    PORT
      LAYER met2 ;
      RECT 154.490 0.000 154.630 0.420 ;
    END
  END r0_rd_out[14]
  PIN r0_rd_out[15]
    DIRECTION OUTPUT ;
    USE SIGNAL ;
    SHAPE ABUTMENT ;
    PORT
      LAYER met2 ;
      RECT 155.870 0.000 156.010 0.420 ;
    END
  END r0_rd_out[15]
  PIN r0_rd_out[16]
    DIRECTION OUTPUT ;
    USE SIGNAL ;
    SHAPE ABUTMENT ;
    PORT
      LAYER met2 ;
      RECT 157.250 0.000 157.390 0.420 ;
    END
  END r0_rd_out[16]
  PIN r0_rd_out[17]
    DIRECTION OUTPUT ;
    USE SIGNAL ;
    SHAPE ABUTMENT ;
    PORT
      LAYER met2 ;
      RECT 158.630 0.000 158.770 0.420 ;
    END
  END r0_rd_out[17]
  PIN r0_rd_out[18]
    DIRECTION OUTPUT ;
    USE SIGNAL ;
    SHAPE ABUTMENT ;
    PORT
      LAYER met2 ;
      RECT 160.010 0.000 160.150 0.420 ;
    END
  END r0_rd_out[18]
  PIN r0_rd_out[19]
    DIRECTION OUTPUT ;
    USE SIGNAL ;
    SHAPE ABUTMENT ;
    PORT
      LAYER met2 ;
      RECT 161.390 0.000 161.530 0.420 ;
    END
  END r0_rd_out[19]
  PIN r0_rd_out[20]
    DIRECTION OUTPUT ;
    USE SIGNAL ;
    SHAPE ABUTMENT ;
    PORT
      LAYER met2 ;
      RECT 162.770 0.000 162.910 0.420 ;
    END
  END r0_rd_out[20]
  PIN r0_rd_out[21]
    DIRECTION OUTPUT ;
    USE SIGNAL ;
    SHAPE ABUTMENT ;
    PORT
      LAYER met2 ;
      RECT 164.150 0.000 164.290 0.420 ;
    END
  END r0_rd_out[21]
  PIN r0_rd_out[22]
    DIRECTION OUTPUT ;
    USE SIGNAL ;
    SHAPE ABUTMENT ;
    PORT
      LAYER met2 ;
      RECT 165.530 0.000 165.670 0.420 ;
    END
  END r0_rd_out[22]
  PIN r0_rd_out[23]
    DIRECTION OUTPUT ;
    USE SIGNAL ;
    SHAPE ABUTMENT ;
    PORT
      LAYER met2 ;
      RECT 166.910 0.000 167.050 0.420 ;
    END
  END r0_rd_out[23]
  PIN r0_rd_out[24]
    DIRECTION OUTPUT ;
    USE SIGNAL ;
    SHAPE ABUTMENT ;
    PORT
      LAYER met2 ;
      RECT 168.290 0.000 168.430 0.420 ;
    END
  END r0_rd_out[24]
  PIN r0_rd_out[25]
    DIRECTION OUTPUT ;
    USE SIGNAL ;
    SHAPE ABUTMENT ;
    PORT
      LAYER met2 ;
      RECT 169.670 0.000 169.810 0.420 ;
    END
  END r0_rd_out[25]
  PIN r0_rd_out[26]
    DIRECTION OUTPUT ;
    USE SIGNAL ;
    SHAPE ABUTMENT ;
    PORT
      LAYER met2 ;
      RECT 171.050 0.000 171.190 0.420 ;
    END
  END r0_rd_out[26]
  PIN r0_rd_out[27]
    DIRECTION OUTPUT ;
    USE SIGNAL ;
    SHAPE ABUTMENT ;
    PORT
      LAYER met2 ;
      RECT 172.430 0.000 172.570 0.420 ;
    END
  END r0_rd_out[27]
  PIN r0_rd_out[28]
    DIRECTION OUTPUT ;
    USE SIGNAL ;
    SHAPE ABUTMENT ;
    PORT
      LAYER met2 ;
      RECT 173.810 0.000 173.950 0.420 ;
    END
  END r0_rd_out[28]
  PIN r0_rd_out[29]
    DIRECTION OUTPUT ;
    USE SIGNAL ;
    SHAPE ABUTMENT ;
    PORT
      LAYER met2 ;
      RECT 175.190 0.000 175.330 0.420 ;
    END
  END r0_rd_out[29]
  PIN r0_rd_out[30]
    DIRECTION OUTPUT ;
    USE SIGNAL ;
    SHAPE ABUTMENT ;
    PORT
      LAYER met2 ;
      RECT 176.570 0.000 176.710 0.420 ;
    END
  END r0_rd_out[30]
  PIN r0_rd_out[31]
    DIRECTION OUTPUT ;
    USE SIGNAL ;
    SHAPE ABUTMENT ;
    PORT
      LAYER met2 ;
      RECT 177.950 0.000 178.090 0.420 ;
    END
  END r0_rd_out[31]
  PIN r0_rd_out[32]
    DIRECTION OUTPUT ;
    USE SIGNAL ;
    SHAPE ABUTMENT ;
    PORT
      LAYER met2 ;
      RECT 179.330 0.000 179.470 0.420 ;
    END
  END r0_rd_out[32]
  PIN r0_rd_out[33]
    DIRECTION OUTPUT ;
    USE SIGNAL ;
    SHAPE ABUTMENT ;
    PORT
      LAYER met2 ;
      RECT 180.710 0.000 180.850 0.420 ;
    END
  END r0_rd_out[33]
  PIN r0_rd_out[34]
    DIRECTION OUTPUT ;
    USE SIGNAL ;
    SHAPE ABUTMENT ;
    PORT
      LAYER met2 ;
      RECT 182.090 0.000 182.230 0.420 ;
    END
  END r0_rd_out[34]
  PIN r0_rd_out[35]
    DIRECTION OUTPUT ;
    USE SIGNAL ;
    SHAPE ABUTMENT ;
    PORT
      LAYER met2 ;
      RECT 183.470 0.000 183.610 0.420 ;
    END
  END r0_rd_out[35]
  PIN r0_rd_out[36]
    DIRECTION OUTPUT ;
    USE SIGNAL ;
    SHAPE ABUTMENT ;
    PORT
      LAYER met2 ;
      RECT 184.850 0.000 184.990 0.420 ;
    END
  END r0_rd_out[36]
  PIN r0_rd_out[37]
    DIRECTION OUTPUT ;
    USE SIGNAL ;
    SHAPE ABUTMENT ;
    PORT
      LAYER met2 ;
      RECT 186.230 0.000 186.370 0.420 ;
    END
  END r0_rd_out[37]
  PIN r0_rd_out[38]
    DIRECTION OUTPUT ;
    USE SIGNAL ;
    SHAPE ABUTMENT ;
    PORT
      LAYER met2 ;
      RECT 187.610 0.000 187.750 0.420 ;
    END
  END r0_rd_out[38]
  PIN r0_rd_out[39]
    DIRECTION OUTPUT ;
    USE SIGNAL ;
    SHAPE ABUTMENT ;
    PORT
      LAYER met2 ;
      RECT 188.990 0.000 189.130 0.420 ;
    END
  END r0_rd_out[39]
  PIN r0_rd_out[40]
    DIRECTION OUTPUT ;
    USE SIGNAL ;
    SHAPE ABUTMENT ;
    PORT
      LAYER met2 ;
      RECT 190.370 0.000 190.510 0.420 ;
    END
  END r0_rd_out[40]
  PIN r0_rd_out[41]
    DIRECTION OUTPUT ;
    USE SIGNAL ;
    SHAPE ABUTMENT ;
    PORT
      LAYER met2 ;
      RECT 191.750 0.000 191.890 0.420 ;
    END
  END r0_rd_out[41]
  PIN r0_rd_out[42]
    DIRECTION OUTPUT ;
    USE SIGNAL ;
    SHAPE ABUTMENT ;
    PORT
      LAYER met2 ;
      RECT 193.130 0.000 193.270 0.420 ;
    END
  END r0_rd_out[42]
  PIN r0_rd_out[43]
    DIRECTION OUTPUT ;
    USE SIGNAL ;
    SHAPE ABUTMENT ;
    PORT
      LAYER met2 ;
      RECT 194.510 0.000 194.650 0.420 ;
    END
  END r0_rd_out[43]
  PIN r0_rd_out[44]
    DIRECTION OUTPUT ;
    USE SIGNAL ;
    SHAPE ABUTMENT ;
    PORT
      LAYER met2 ;
      RECT 195.890 0.000 196.030 0.420 ;
    END
  END r0_rd_out[44]
  PIN r0_rd_out[45]
    DIRECTION OUTPUT ;
    USE SIGNAL ;
    SHAPE ABUTMENT ;
    PORT
      LAYER met2 ;
      RECT 197.270 0.000 197.410 0.420 ;
    END
  END r0_rd_out[45]
  PIN r0_rd_out[46]
    DIRECTION OUTPUT ;
    USE SIGNAL ;
    SHAPE ABUTMENT ;
    PORT
      LAYER met2 ;
      RECT 198.650 0.000 198.790 0.420 ;
    END
  END r0_rd_out[46]
  PIN r0_rd_out[47]
    DIRECTION OUTPUT ;
    USE SIGNAL ;
    SHAPE ABUTMENT ;
    PORT
      LAYER met2 ;
      RECT 200.030 0.000 200.170 0.420 ;
    END
  END r0_rd_out[47]
  PIN r0_rd_out[48]
    DIRECTION OUTPUT ;
    USE SIGNAL ;
    SHAPE ABUTMENT ;
    PORT
      LAYER met2 ;
      RECT 201.410 0.000 201.550 0.420 ;
    END
  END r0_rd_out[48]
  PIN r0_rd_out[49]
    DIRECTION OUTPUT ;
    USE SIGNAL ;
    SHAPE ABUTMENT ;
    PORT
      LAYER met2 ;
      RECT 202.790 0.000 202.930 0.420 ;
    END
  END r0_rd_out[49]
  PIN r0_rd_out[50]
    DIRECTION OUTPUT ;
    USE SIGNAL ;
    SHAPE ABUTMENT ;
    PORT
      LAYER met2 ;
      RECT 204.170 0.000 204.310 0.420 ;
    END
  END r0_rd_out[50]
  PIN r0_rd_out[51]
    DIRECTION OUTPUT ;
    USE SIGNAL ;
    SHAPE ABUTMENT ;
    PORT
      LAYER met2 ;
      RECT 205.550 0.000 205.690 0.420 ;
    END
  END r0_rd_out[51]
  PIN r0_rd_out[52]
    DIRECTION OUTPUT ;
    USE SIGNAL ;
    SHAPE ABUTMENT ;
    PORT
      LAYER met2 ;
      RECT 206.930 0.000 207.070 0.420 ;
    END
  END r0_rd_out[52]
  PIN r0_rd_out[53]
    DIRECTION OUTPUT ;
    USE SIGNAL ;
    SHAPE ABUTMENT ;
    PORT
      LAYER met2 ;
      RECT 208.310 0.000 208.450 0.420 ;
    END
  END r0_rd_out[53]
  PIN r0_rd_out[54]
    DIRECTION OUTPUT ;
    USE SIGNAL ;
    SHAPE ABUTMENT ;
    PORT
      LAYER met2 ;
      RECT 209.690 0.000 209.830 0.420 ;
    END
  END r0_rd_out[54]
  PIN r0_rd_out[55]
    DIRECTION OUTPUT ;
    USE SIGNAL ;
    SHAPE ABUTMENT ;
    PORT
      LAYER met2 ;
      RECT 211.070 0.000 211.210 0.420 ;
    END
  END r0_rd_out[55]
  PIN r0_rd_out[56]
    DIRECTION OUTPUT ;
    USE SIGNAL ;
    SHAPE ABUTMENT ;
    PORT
      LAYER met2 ;
      RECT 212.450 0.000 212.590 0.420 ;
    END
  END r0_rd_out[56]
  PIN r0_rd_out[57]
    DIRECTION OUTPUT ;
    USE SIGNAL ;
    SHAPE ABUTMENT ;
    PORT
      LAYER met2 ;
      RECT 213.830 0.000 213.970 0.420 ;
    END
  END r0_rd_out[57]
  PIN r0_rd_out[58]
    DIRECTION OUTPUT ;
    USE SIGNAL ;
    SHAPE ABUTMENT ;
    PORT
      LAYER met2 ;
      RECT 215.210 0.000 215.350 0.420 ;
    END
  END r0_rd_out[58]
  PIN r0_rd_out[59]
    DIRECTION OUTPUT ;
    USE SIGNAL ;
    SHAPE ABUTMENT ;
    PORT
      LAYER met2 ;
      RECT 216.590 0.000 216.730 0.420 ;
    END
  END r0_rd_out[59]
  PIN r0_rd_out[60]
    DIRECTION OUTPUT ;
    USE SIGNAL ;
    SHAPE ABUTMENT ;
    PORT
      LAYER met2 ;
      RECT 217.970 0.000 218.110 0.420 ;
    END
  END r0_rd_out[60]
  PIN r0_rd_out[61]
    DIRECTION OUTPUT ;
    USE SIGNAL ;
    SHAPE ABUTMENT ;
    PORT
      LAYER met2 ;
      RECT 219.350 0.000 219.490 0.420 ;
    END
  END r0_rd_out[61]
  PIN r0_rd_out[62]
    DIRECTION OUTPUT ;
    USE SIGNAL ;
    SHAPE ABUTMENT ;
    PORT
      LAYER met2 ;
      RECT 220.730 0.000 220.870 0.420 ;
    END
  END r0_rd_out[62]
  PIN r0_rd_out[63]
    DIRECTION OUTPUT ;
    USE SIGNAL ;
    SHAPE ABUTMENT ;
    PORT
      LAYER met2 ;
      RECT 222.110 0.000 222.250 0.420 ;
    END
  END r0_rd_out[63]
  PIN r0_rd_out[64]
    DIRECTION OUTPUT ;
    USE SIGNAL ;
    SHAPE ABUTMENT ;
    PORT
      LAYER met2 ;
      RECT 223.490 0.000 223.630 0.420 ;
    END
  END r0_rd_out[64]
  PIN r0_rd_out[65]
    DIRECTION OUTPUT ;
    USE SIGNAL ;
    SHAPE ABUTMENT ;
    PORT
      LAYER met2 ;
      RECT 224.870 0.000 225.010 0.420 ;
    END
  END r0_rd_out[65]
  PIN r0_rd_out[66]
    DIRECTION OUTPUT ;
    USE SIGNAL ;
    SHAPE ABUTMENT ;
    PORT
      LAYER met2 ;
      RECT 226.250 0.000 226.390 0.420 ;
    END
  END r0_rd_out[66]
  PIN r0_rd_out[67]
    DIRECTION OUTPUT ;
    USE SIGNAL ;
    SHAPE ABUTMENT ;
    PORT
      LAYER met2 ;
      RECT 227.630 0.000 227.770 0.420 ;
    END
  END r0_rd_out[67]
  PIN r0_rd_out[68]
    DIRECTION OUTPUT ;
    USE SIGNAL ;
    SHAPE ABUTMENT ;
    PORT
      LAYER met2 ;
      RECT 229.010 0.000 229.150 0.420 ;
    END
  END r0_rd_out[68]
  PIN r0_rd_out[69]
    DIRECTION OUTPUT ;
    USE SIGNAL ;
    SHAPE ABUTMENT ;
    PORT
      LAYER met2 ;
      RECT 230.390 0.000 230.530 0.420 ;
    END
  END r0_rd_out[69]
  PIN r0_rd_out[70]
    DIRECTION OUTPUT ;
    USE SIGNAL ;
    SHAPE ABUTMENT ;
    PORT
      LAYER met2 ;
      RECT 231.770 0.000 231.910 0.420 ;
    END
  END r0_rd_out[70]
  PIN r0_rd_out[71]
    DIRECTION OUTPUT ;
    USE SIGNAL ;
    SHAPE ABUTMENT ;
    PORT
      LAYER met2 ;
      RECT 233.150 0.000 233.290 0.420 ;
    END
  END r0_rd_out[71]
  PIN r0_rd_out[72]
    DIRECTION OUTPUT ;
    USE SIGNAL ;
    SHAPE ABUTMENT ;
    PORT
      LAYER met2 ;
      RECT 234.530 0.000 234.670 0.420 ;
    END
  END r0_rd_out[72]
  PIN r0_rd_out[73]
    DIRECTION OUTPUT ;
    USE SIGNAL ;
    SHAPE ABUTMENT ;
    PORT
      LAYER met2 ;
      RECT 235.910 0.000 236.050 0.420 ;
    END
  END r0_rd_out[73]
  PIN r0_rd_out[74]
    DIRECTION OUTPUT ;
    USE SIGNAL ;
    SHAPE ABUTMENT ;
    PORT
      LAYER met2 ;
      RECT 237.290 0.000 237.430 0.420 ;
    END
  END r0_rd_out[74]
  PIN r0_rd_out[75]
    DIRECTION OUTPUT ;
    USE SIGNAL ;
    SHAPE ABUTMENT ;
    PORT
      LAYER met2 ;
      RECT 238.670 0.000 238.810 0.420 ;
    END
  END r0_rd_out[75]
  PIN r0_rd_out[76]
    DIRECTION OUTPUT ;
    USE SIGNAL ;
    SHAPE ABUTMENT ;
    PORT
      LAYER met2 ;
      RECT 240.050 0.000 240.190 0.420 ;
    END
  END r0_rd_out[76]
  PIN r0_rd_out[77]
    DIRECTION OUTPUT ;
    USE SIGNAL ;
    SHAPE ABUTMENT ;
    PORT
      LAYER met2 ;
      RECT 241.430 0.000 241.570 0.420 ;
    END
  END r0_rd_out[77]
  PIN r0_rd_out[78]
    DIRECTION OUTPUT ;
    USE SIGNAL ;
    SHAPE ABUTMENT ;
    PORT
      LAYER met2 ;
      RECT 242.810 0.000 242.950 0.420 ;
    END
  END r0_rd_out[78]
  PIN r0_rd_out[79]
    DIRECTION OUTPUT ;
    USE SIGNAL ;
    SHAPE ABUTMENT ;
    PORT
      LAYER met2 ;
      RECT 244.190 0.000 244.330 0.420 ;
    END
  END r0_rd_out[79]
  PIN r0_rd_out[80]
    DIRECTION OUTPUT ;
    USE SIGNAL ;
    SHAPE ABUTMENT ;
    PORT
      LAYER met2 ;
      RECT 245.570 0.000 245.710 0.420 ;
    END
  END r0_rd_out[80]
  PIN r0_rd_out[81]
    DIRECTION OUTPUT ;
    USE SIGNAL ;
    SHAPE ABUTMENT ;
    PORT
      LAYER met2 ;
      RECT 246.950 0.000 247.090 0.420 ;
    END
  END r0_rd_out[81]
  PIN r0_rd_out[82]
    DIRECTION OUTPUT ;
    USE SIGNAL ;
    SHAPE ABUTMENT ;
    PORT
      LAYER met2 ;
      RECT 248.330 0.000 248.470 0.420 ;
    END
  END r0_rd_out[82]
  PIN r0_rd_out[83]
    DIRECTION OUTPUT ;
    USE SIGNAL ;
    SHAPE ABUTMENT ;
    PORT
      LAYER met2 ;
      RECT 249.710 0.000 249.850 0.420 ;
    END
  END r0_rd_out[83]
  PIN r0_rd_out[84]
    DIRECTION OUTPUT ;
    USE SIGNAL ;
    SHAPE ABUTMENT ;
    PORT
      LAYER met2 ;
      RECT 251.090 0.000 251.230 0.420 ;
    END
  END r0_rd_out[84]
  PIN r0_rd_out[85]
    DIRECTION OUTPUT ;
    USE SIGNAL ;
    SHAPE ABUTMENT ;
    PORT
      LAYER met2 ;
      RECT 252.470 0.000 252.610 0.420 ;
    END
  END r0_rd_out[85]
  PIN r0_rd_out[86]
    DIRECTION OUTPUT ;
    USE SIGNAL ;
    SHAPE ABUTMENT ;
    PORT
      LAYER met2 ;
      RECT 253.850 0.000 253.990 0.420 ;
    END
  END r0_rd_out[86]
  PIN r0_rd_out[87]
    DIRECTION OUTPUT ;
    USE SIGNAL ;
    SHAPE ABUTMENT ;
    PORT
      LAYER met2 ;
      RECT 255.230 0.000 255.370 0.420 ;
    END
  END r0_rd_out[87]
  PIN r0_rd_out[88]
    DIRECTION OUTPUT ;
    USE SIGNAL ;
    SHAPE ABUTMENT ;
    PORT
      LAYER met2 ;
      RECT 256.610 0.000 256.750 0.420 ;
    END
  END r0_rd_out[88]
  PIN r0_rd_out[89]
    DIRECTION OUTPUT ;
    USE SIGNAL ;
    SHAPE ABUTMENT ;
    PORT
      LAYER met2 ;
      RECT 257.990 0.000 258.130 0.420 ;
    END
  END r0_rd_out[89]
  PIN r0_rd_out[90]
    DIRECTION OUTPUT ;
    USE SIGNAL ;
    SHAPE ABUTMENT ;
    PORT
      LAYER met2 ;
      RECT 259.370 0.000 259.510 0.420 ;
    END
  END r0_rd_out[90]
  PIN r0_rd_out[91]
    DIRECTION OUTPUT ;
    USE SIGNAL ;
    SHAPE ABUTMENT ;
    PORT
      LAYER met2 ;
      RECT 260.750 0.000 260.890 0.420 ;
    END
  END r0_rd_out[91]
  PIN r0_rd_out[92]
    DIRECTION OUTPUT ;
    USE SIGNAL ;
    SHAPE ABUTMENT ;
    PORT
      LAYER met2 ;
      RECT 262.130 0.000 262.270 0.420 ;
    END
  END r0_rd_out[92]
  PIN r0_rd_out[93]
    DIRECTION OUTPUT ;
    USE SIGNAL ;
    SHAPE ABUTMENT ;
    PORT
      LAYER met2 ;
      RECT 263.510 0.000 263.650 0.420 ;
    END
  END r0_rd_out[93]
  PIN r0_rd_out[94]
    DIRECTION OUTPUT ;
    USE SIGNAL ;
    SHAPE ABUTMENT ;
    PORT
      LAYER met2 ;
      RECT 264.890 0.000 265.030 0.420 ;
    END
  END r0_rd_out[94]
  PIN r0_rd_out[95]
    DIRECTION OUTPUT ;
    USE SIGNAL ;
    SHAPE ABUTMENT ;
    PORT
      LAYER met2 ;
      RECT 266.270 0.000 266.410 0.420 ;
    END
  END r0_rd_out[95]
  PIN r0_rd_out[96]
    DIRECTION OUTPUT ;
    USE SIGNAL ;
    SHAPE ABUTMENT ;
    PORT
      LAYER met2 ;
      RECT 267.650 0.000 267.790 0.420 ;
    END
  END r0_rd_out[96]
  PIN r0_rd_out[97]
    DIRECTION OUTPUT ;
    USE SIGNAL ;
    SHAPE ABUTMENT ;
    PORT
      LAYER met2 ;
      RECT 135.170 606.140 135.310 606.560 ;
    END
  END r0_rd_out[97]
  PIN r0_rd_out[98]
    DIRECTION OUTPUT ;
    USE SIGNAL ;
    SHAPE ABUTMENT ;
    PORT
      LAYER met2 ;
      RECT 136.550 606.140 136.690 606.560 ;
    END
  END r0_rd_out[98]
  PIN r0_rd_out[99]
    DIRECTION OUTPUT ;
    USE SIGNAL ;
    SHAPE ABUTMENT ;
    PORT
      LAYER met2 ;
      RECT 137.930 606.140 138.070 606.560 ;
    END
  END r0_rd_out[99]
  PIN r0_rd_out[100]
    DIRECTION OUTPUT ;
    USE SIGNAL ;
    SHAPE ABUTMENT ;
    PORT
      LAYER met2 ;
      RECT 139.310 606.140 139.450 606.560 ;
    END
  END r0_rd_out[100]
  PIN r0_rd_out[101]
    DIRECTION OUTPUT ;
    USE SIGNAL ;
    SHAPE ABUTMENT ;
    PORT
      LAYER met2 ;
      RECT 140.690 606.140 140.830 606.560 ;
    END
  END r0_rd_out[101]
  PIN r0_rd_out[102]
    DIRECTION OUTPUT ;
    USE SIGNAL ;
    SHAPE ABUTMENT ;
    PORT
      LAYER met2 ;
      RECT 142.070 606.140 142.210 606.560 ;
    END
  END r0_rd_out[102]
  PIN r0_rd_out[103]
    DIRECTION OUTPUT ;
    USE SIGNAL ;
    SHAPE ABUTMENT ;
    PORT
      LAYER met2 ;
      RECT 143.450 606.140 143.590 606.560 ;
    END
  END r0_rd_out[103]
  PIN r0_rd_out[104]
    DIRECTION OUTPUT ;
    USE SIGNAL ;
    SHAPE ABUTMENT ;
    PORT
      LAYER met2 ;
      RECT 144.830 606.140 144.970 606.560 ;
    END
  END r0_rd_out[104]
  PIN r0_rd_out[105]
    DIRECTION OUTPUT ;
    USE SIGNAL ;
    SHAPE ABUTMENT ;
    PORT
      LAYER met2 ;
      RECT 146.210 606.140 146.350 606.560 ;
    END
  END r0_rd_out[105]
  PIN r0_rd_out[106]
    DIRECTION OUTPUT ;
    USE SIGNAL ;
    SHAPE ABUTMENT ;
    PORT
      LAYER met2 ;
      RECT 147.590 606.140 147.730 606.560 ;
    END
  END r0_rd_out[106]
  PIN r0_rd_out[107]
    DIRECTION OUTPUT ;
    USE SIGNAL ;
    SHAPE ABUTMENT ;
    PORT
      LAYER met2 ;
      RECT 148.970 606.140 149.110 606.560 ;
    END
  END r0_rd_out[107]
  PIN r0_rd_out[108]
    DIRECTION OUTPUT ;
    USE SIGNAL ;
    SHAPE ABUTMENT ;
    PORT
      LAYER met2 ;
      RECT 150.350 606.140 150.490 606.560 ;
    END
  END r0_rd_out[108]
  PIN r0_rd_out[109]
    DIRECTION OUTPUT ;
    USE SIGNAL ;
    SHAPE ABUTMENT ;
    PORT
      LAYER met2 ;
      RECT 151.730 606.140 151.870 606.560 ;
    END
  END r0_rd_out[109]
  PIN r0_rd_out[110]
    DIRECTION OUTPUT ;
    USE SIGNAL ;
    SHAPE ABUTMENT ;
    PORT
      LAYER met2 ;
      RECT 153.110 606.140 153.250 606.560 ;
    END
  END r0_rd_out[110]
  PIN r0_rd_out[111]
    DIRECTION OUTPUT ;
    USE SIGNAL ;
    SHAPE ABUTMENT ;
    PORT
      LAYER met2 ;
      RECT 154.490 606.140 154.630 606.560 ;
    END
  END r0_rd_out[111]
  PIN r0_rd_out[112]
    DIRECTION OUTPUT ;
    USE SIGNAL ;
    SHAPE ABUTMENT ;
    PORT
      LAYER met2 ;
      RECT 155.870 606.140 156.010 606.560 ;
    END
  END r0_rd_out[112]
  PIN r0_rd_out[113]
    DIRECTION OUTPUT ;
    USE SIGNAL ;
    SHAPE ABUTMENT ;
    PORT
      LAYER met2 ;
      RECT 157.250 606.140 157.390 606.560 ;
    END
  END r0_rd_out[113]
  PIN r0_rd_out[114]
    DIRECTION OUTPUT ;
    USE SIGNAL ;
    SHAPE ABUTMENT ;
    PORT
      LAYER met2 ;
      RECT 158.630 606.140 158.770 606.560 ;
    END
  END r0_rd_out[114]
  PIN r0_rd_out[115]
    DIRECTION OUTPUT ;
    USE SIGNAL ;
    SHAPE ABUTMENT ;
    PORT
      LAYER met2 ;
      RECT 160.010 606.140 160.150 606.560 ;
    END
  END r0_rd_out[115]
  PIN r0_rd_out[116]
    DIRECTION OUTPUT ;
    USE SIGNAL ;
    SHAPE ABUTMENT ;
    PORT
      LAYER met2 ;
      RECT 161.390 606.140 161.530 606.560 ;
    END
  END r0_rd_out[116]
  PIN r0_rd_out[117]
    DIRECTION OUTPUT ;
    USE SIGNAL ;
    SHAPE ABUTMENT ;
    PORT
      LAYER met2 ;
      RECT 162.770 606.140 162.910 606.560 ;
    END
  END r0_rd_out[117]
  PIN r0_rd_out[118]
    DIRECTION OUTPUT ;
    USE SIGNAL ;
    SHAPE ABUTMENT ;
    PORT
      LAYER met2 ;
      RECT 164.150 606.140 164.290 606.560 ;
    END
  END r0_rd_out[118]
  PIN r0_rd_out[119]
    DIRECTION OUTPUT ;
    USE SIGNAL ;
    SHAPE ABUTMENT ;
    PORT
      LAYER met2 ;
      RECT 165.530 606.140 165.670 606.560 ;
    END
  END r0_rd_out[119]
  PIN r0_rd_out[120]
    DIRECTION OUTPUT ;
    USE SIGNAL ;
    SHAPE ABUTMENT ;
    PORT
      LAYER met2 ;
      RECT 166.910 606.140 167.050 606.560 ;
    END
  END r0_rd_out[120]
  PIN r0_rd_out[121]
    DIRECTION OUTPUT ;
    USE SIGNAL ;
    SHAPE ABUTMENT ;
    PORT
      LAYER met2 ;
      RECT 168.290 606.140 168.430 606.560 ;
    END
  END r0_rd_out[121]
  PIN r0_rd_out[122]
    DIRECTION OUTPUT ;
    USE SIGNAL ;
    SHAPE ABUTMENT ;
    PORT
      LAYER met2 ;
      RECT 169.670 606.140 169.810 606.560 ;
    END
  END r0_rd_out[122]
  PIN r0_rd_out[123]
    DIRECTION OUTPUT ;
    USE SIGNAL ;
    SHAPE ABUTMENT ;
    PORT
      LAYER met2 ;
      RECT 171.050 606.140 171.190 606.560 ;
    END
  END r0_rd_out[123]
  PIN r0_rd_out[124]
    DIRECTION OUTPUT ;
    USE SIGNAL ;
    SHAPE ABUTMENT ;
    PORT
      LAYER met2 ;
      RECT 172.430 606.140 172.570 606.560 ;
    END
  END r0_rd_out[124]
  PIN r0_rd_out[125]
    DIRECTION OUTPUT ;
    USE SIGNAL ;
    SHAPE ABUTMENT ;
    PORT
      LAYER met2 ;
      RECT 173.810 606.140 173.950 606.560 ;
    END
  END r0_rd_out[125]
  PIN r0_rd_out[126]
    DIRECTION OUTPUT ;
    USE SIGNAL ;
    SHAPE ABUTMENT ;
    PORT
      LAYER met2 ;
      RECT 175.190 606.140 175.330 606.560 ;
    END
  END r0_rd_out[126]
  PIN r0_rd_out[127]
    DIRECTION OUTPUT ;
    USE SIGNAL ;
    SHAPE ABUTMENT ;
    PORT
      LAYER met2 ;
      RECT 176.570 606.140 176.710 606.560 ;
    END
  END r0_rd_out[127]
  PIN r0_rd_out[128]
    DIRECTION OUTPUT ;
    USE SIGNAL ;
    SHAPE ABUTMENT ;
    PORT
      LAYER met2 ;
      RECT 177.950 606.140 178.090 606.560 ;
    END
  END r0_rd_out[128]
  PIN r0_rd_out[129]
    DIRECTION OUTPUT ;
    USE SIGNAL ;
    SHAPE ABUTMENT ;
    PORT
      LAYER met2 ;
      RECT 179.330 606.140 179.470 606.560 ;
    END
  END r0_rd_out[129]
  PIN r0_rd_out[130]
    DIRECTION OUTPUT ;
    USE SIGNAL ;
    SHAPE ABUTMENT ;
    PORT
      LAYER met2 ;
      RECT 180.710 606.140 180.850 606.560 ;
    END
  END r0_rd_out[130]
  PIN r0_rd_out[131]
    DIRECTION OUTPUT ;
    USE SIGNAL ;
    SHAPE ABUTMENT ;
    PORT
      LAYER met2 ;
      RECT 182.090 606.140 182.230 606.560 ;
    END
  END r0_rd_out[131]
  PIN r0_rd_out[132]
    DIRECTION OUTPUT ;
    USE SIGNAL ;
    SHAPE ABUTMENT ;
    PORT
      LAYER met2 ;
      RECT 183.470 606.140 183.610 606.560 ;
    END
  END r0_rd_out[132]
  PIN r0_rd_out[133]
    DIRECTION OUTPUT ;
    USE SIGNAL ;
    SHAPE ABUTMENT ;
    PORT
      LAYER met2 ;
      RECT 184.850 606.140 184.990 606.560 ;
    END
  END r0_rd_out[133]
  PIN r0_rd_out[134]
    DIRECTION OUTPUT ;
    USE SIGNAL ;
    SHAPE ABUTMENT ;
    PORT
      LAYER met2 ;
      RECT 186.230 606.140 186.370 606.560 ;
    END
  END r0_rd_out[134]
  PIN r0_rd_out[135]
    DIRECTION OUTPUT ;
    USE SIGNAL ;
    SHAPE ABUTMENT ;
    PORT
      LAYER met2 ;
      RECT 187.610 606.140 187.750 606.560 ;
    END
  END r0_rd_out[135]
  PIN r0_rd_out[136]
    DIRECTION OUTPUT ;
    USE SIGNAL ;
    SHAPE ABUTMENT ;
    PORT
      LAYER met2 ;
      RECT 188.990 606.140 189.130 606.560 ;
    END
  END r0_rd_out[136]
  PIN r0_rd_out[137]
    DIRECTION OUTPUT ;
    USE SIGNAL ;
    SHAPE ABUTMENT ;
    PORT
      LAYER met2 ;
      RECT 190.370 606.140 190.510 606.560 ;
    END
  END r0_rd_out[137]
  PIN r0_rd_out[138]
    DIRECTION OUTPUT ;
    USE SIGNAL ;
    SHAPE ABUTMENT ;
    PORT
      LAYER met2 ;
      RECT 191.750 606.140 191.890 606.560 ;
    END
  END r0_rd_out[138]
  PIN r0_rd_out[139]
    DIRECTION OUTPUT ;
    USE SIGNAL ;
    SHAPE ABUTMENT ;
    PORT
      LAYER met2 ;
      RECT 193.130 606.140 193.270 606.560 ;
    END
  END r0_rd_out[139]
  PIN r0_rd_out[140]
    DIRECTION OUTPUT ;
    USE SIGNAL ;
    SHAPE ABUTMENT ;
    PORT
      LAYER met2 ;
      RECT 194.510 606.140 194.650 606.560 ;
    END
  END r0_rd_out[140]
  PIN r0_rd_out[141]
    DIRECTION OUTPUT ;
    USE SIGNAL ;
    SHAPE ABUTMENT ;
    PORT
      LAYER met2 ;
      RECT 195.890 606.140 196.030 606.560 ;
    END
  END r0_rd_out[141]
  PIN r0_rd_out[142]
    DIRECTION OUTPUT ;
    USE SIGNAL ;
    SHAPE ABUTMENT ;
    PORT
      LAYER met2 ;
      RECT 197.270 606.140 197.410 606.560 ;
    END
  END r0_rd_out[142]
  PIN r0_rd_out[143]
    DIRECTION OUTPUT ;
    USE SIGNAL ;
    SHAPE ABUTMENT ;
    PORT
      LAYER met2 ;
      RECT 198.650 606.140 198.790 606.560 ;
    END
  END r0_rd_out[143]
  PIN r0_rd_out[144]
    DIRECTION OUTPUT ;
    USE SIGNAL ;
    SHAPE ABUTMENT ;
    PORT
      LAYER met2 ;
      RECT 200.030 606.140 200.170 606.560 ;
    END
  END r0_rd_out[144]
  PIN r0_rd_out[145]
    DIRECTION OUTPUT ;
    USE SIGNAL ;
    SHAPE ABUTMENT ;
    PORT
      LAYER met2 ;
      RECT 201.410 606.140 201.550 606.560 ;
    END
  END r0_rd_out[145]
  PIN r0_rd_out[146]
    DIRECTION OUTPUT ;
    USE SIGNAL ;
    SHAPE ABUTMENT ;
    PORT
      LAYER met2 ;
      RECT 202.790 606.140 202.930 606.560 ;
    END
  END r0_rd_out[146]
  PIN r0_rd_out[147]
    DIRECTION OUTPUT ;
    USE SIGNAL ;
    SHAPE ABUTMENT ;
    PORT
      LAYER met2 ;
      RECT 204.170 606.140 204.310 606.560 ;
    END
  END r0_rd_out[147]
  PIN r0_rd_out[148]
    DIRECTION OUTPUT ;
    USE SIGNAL ;
    SHAPE ABUTMENT ;
    PORT
      LAYER met2 ;
      RECT 205.550 606.140 205.690 606.560 ;
    END
  END r0_rd_out[148]
  PIN r0_rd_out[149]
    DIRECTION OUTPUT ;
    USE SIGNAL ;
    SHAPE ABUTMENT ;
    PORT
      LAYER met2 ;
      RECT 206.930 606.140 207.070 606.560 ;
    END
  END r0_rd_out[149]
  PIN r0_rd_out[150]
    DIRECTION OUTPUT ;
    USE SIGNAL ;
    SHAPE ABUTMENT ;
    PORT
      LAYER met2 ;
      RECT 208.310 606.140 208.450 606.560 ;
    END
  END r0_rd_out[150]
  PIN r0_rd_out[151]
    DIRECTION OUTPUT ;
    USE SIGNAL ;
    SHAPE ABUTMENT ;
    PORT
      LAYER met2 ;
      RECT 209.690 606.140 209.830 606.560 ;
    END
  END r0_rd_out[151]
  PIN r0_rd_out[152]
    DIRECTION OUTPUT ;
    USE SIGNAL ;
    SHAPE ABUTMENT ;
    PORT
      LAYER met2 ;
      RECT 211.070 606.140 211.210 606.560 ;
    END
  END r0_rd_out[152]
  PIN r0_rd_out[153]
    DIRECTION OUTPUT ;
    USE SIGNAL ;
    SHAPE ABUTMENT ;
    PORT
      LAYER met2 ;
      RECT 212.450 606.140 212.590 606.560 ;
    END
  END r0_rd_out[153]
  PIN r0_rd_out[154]
    DIRECTION OUTPUT ;
    USE SIGNAL ;
    SHAPE ABUTMENT ;
    PORT
      LAYER met2 ;
      RECT 213.830 606.140 213.970 606.560 ;
    END
  END r0_rd_out[154]
  PIN r0_rd_out[155]
    DIRECTION OUTPUT ;
    USE SIGNAL ;
    SHAPE ABUTMENT ;
    PORT
      LAYER met2 ;
      RECT 215.210 606.140 215.350 606.560 ;
    END
  END r0_rd_out[155]
  PIN r0_rd_out[156]
    DIRECTION OUTPUT ;
    USE SIGNAL ;
    SHAPE ABUTMENT ;
    PORT
      LAYER met2 ;
      RECT 216.590 606.140 216.730 606.560 ;
    END
  END r0_rd_out[156]
  PIN r0_rd_out[157]
    DIRECTION OUTPUT ;
    USE SIGNAL ;
    SHAPE ABUTMENT ;
    PORT
      LAYER met2 ;
      RECT 217.970 606.140 218.110 606.560 ;
    END
  END r0_rd_out[157]
  PIN r0_rd_out[158]
    DIRECTION OUTPUT ;
    USE SIGNAL ;
    SHAPE ABUTMENT ;
    PORT
      LAYER met2 ;
      RECT 219.350 606.140 219.490 606.560 ;
    END
  END r0_rd_out[158]
  PIN r0_rd_out[159]
    DIRECTION OUTPUT ;
    USE SIGNAL ;
    SHAPE ABUTMENT ;
    PORT
      LAYER met2 ;
      RECT 220.730 606.140 220.870 606.560 ;
    END
  END r0_rd_out[159]
  PIN r0_rd_out[160]
    DIRECTION OUTPUT ;
    USE SIGNAL ;
    SHAPE ABUTMENT ;
    PORT
      LAYER met2 ;
      RECT 222.110 606.140 222.250 606.560 ;
    END
  END r0_rd_out[160]
  PIN r0_rd_out[161]
    DIRECTION OUTPUT ;
    USE SIGNAL ;
    SHAPE ABUTMENT ;
    PORT
      LAYER met2 ;
      RECT 223.490 606.140 223.630 606.560 ;
    END
  END r0_rd_out[161]
  PIN r0_rd_out[162]
    DIRECTION OUTPUT ;
    USE SIGNAL ;
    SHAPE ABUTMENT ;
    PORT
      LAYER met2 ;
      RECT 224.870 606.140 225.010 606.560 ;
    END
  END r0_rd_out[162]
  PIN r0_rd_out[163]
    DIRECTION OUTPUT ;
    USE SIGNAL ;
    SHAPE ABUTMENT ;
    PORT
      LAYER met2 ;
      RECT 226.250 606.140 226.390 606.560 ;
    END
  END r0_rd_out[163]
  PIN r0_rd_out[164]
    DIRECTION OUTPUT ;
    USE SIGNAL ;
    SHAPE ABUTMENT ;
    PORT
      LAYER met2 ;
      RECT 227.630 606.140 227.770 606.560 ;
    END
  END r0_rd_out[164]
  PIN r0_rd_out[165]
    DIRECTION OUTPUT ;
    USE SIGNAL ;
    SHAPE ABUTMENT ;
    PORT
      LAYER met2 ;
      RECT 229.010 606.140 229.150 606.560 ;
    END
  END r0_rd_out[165]
  PIN r0_rd_out[166]
    DIRECTION OUTPUT ;
    USE SIGNAL ;
    SHAPE ABUTMENT ;
    PORT
      LAYER met2 ;
      RECT 230.390 606.140 230.530 606.560 ;
    END
  END r0_rd_out[166]
  PIN r0_rd_out[167]
    DIRECTION OUTPUT ;
    USE SIGNAL ;
    SHAPE ABUTMENT ;
    PORT
      LAYER met2 ;
      RECT 231.770 606.140 231.910 606.560 ;
    END
  END r0_rd_out[167]
  PIN r0_rd_out[168]
    DIRECTION OUTPUT ;
    USE SIGNAL ;
    SHAPE ABUTMENT ;
    PORT
      LAYER met2 ;
      RECT 233.150 606.140 233.290 606.560 ;
    END
  END r0_rd_out[168]
  PIN r0_rd_out[169]
    DIRECTION OUTPUT ;
    USE SIGNAL ;
    SHAPE ABUTMENT ;
    PORT
      LAYER met2 ;
      RECT 234.530 606.140 234.670 606.560 ;
    END
  END r0_rd_out[169]
  PIN r0_rd_out[170]
    DIRECTION OUTPUT ;
    USE SIGNAL ;
    SHAPE ABUTMENT ;
    PORT
      LAYER met2 ;
      RECT 235.910 606.140 236.050 606.560 ;
    END
  END r0_rd_out[170]
  PIN r0_rd_out[171]
    DIRECTION OUTPUT ;
    USE SIGNAL ;
    SHAPE ABUTMENT ;
    PORT
      LAYER met2 ;
      RECT 237.290 606.140 237.430 606.560 ;
    END
  END r0_rd_out[171]
  PIN r0_rd_out[172]
    DIRECTION OUTPUT ;
    USE SIGNAL ;
    SHAPE ABUTMENT ;
    PORT
      LAYER met2 ;
      RECT 238.670 606.140 238.810 606.560 ;
    END
  END r0_rd_out[172]
  PIN r0_rd_out[173]
    DIRECTION OUTPUT ;
    USE SIGNAL ;
    SHAPE ABUTMENT ;
    PORT
      LAYER met2 ;
      RECT 240.050 606.140 240.190 606.560 ;
    END
  END r0_rd_out[173]
  PIN r0_rd_out[174]
    DIRECTION OUTPUT ;
    USE SIGNAL ;
    SHAPE ABUTMENT ;
    PORT
      LAYER met2 ;
      RECT 241.430 606.140 241.570 606.560 ;
    END
  END r0_rd_out[174]
  PIN r0_rd_out[175]
    DIRECTION OUTPUT ;
    USE SIGNAL ;
    SHAPE ABUTMENT ;
    PORT
      LAYER met2 ;
      RECT 242.810 606.140 242.950 606.560 ;
    END
  END r0_rd_out[175]
  PIN r0_rd_out[176]
    DIRECTION OUTPUT ;
    USE SIGNAL ;
    SHAPE ABUTMENT ;
    PORT
      LAYER met2 ;
      RECT 244.190 606.140 244.330 606.560 ;
    END
  END r0_rd_out[176]
  PIN r0_rd_out[177]
    DIRECTION OUTPUT ;
    USE SIGNAL ;
    SHAPE ABUTMENT ;
    PORT
      LAYER met2 ;
      RECT 245.570 606.140 245.710 606.560 ;
    END
  END r0_rd_out[177]
  PIN r0_rd_out[178]
    DIRECTION OUTPUT ;
    USE SIGNAL ;
    SHAPE ABUTMENT ;
    PORT
      LAYER met2 ;
      RECT 246.950 606.140 247.090 606.560 ;
    END
  END r0_rd_out[178]
  PIN r0_rd_out[179]
    DIRECTION OUTPUT ;
    USE SIGNAL ;
    SHAPE ABUTMENT ;
    PORT
      LAYER met2 ;
      RECT 248.330 606.140 248.470 606.560 ;
    END
  END r0_rd_out[179]
  PIN r0_rd_out[180]
    DIRECTION OUTPUT ;
    USE SIGNAL ;
    SHAPE ABUTMENT ;
    PORT
      LAYER met2 ;
      RECT 249.710 606.140 249.850 606.560 ;
    END
  END r0_rd_out[180]
  PIN r0_rd_out[181]
    DIRECTION OUTPUT ;
    USE SIGNAL ;
    SHAPE ABUTMENT ;
    PORT
      LAYER met2 ;
      RECT 251.090 606.140 251.230 606.560 ;
    END
  END r0_rd_out[181]
  PIN r0_rd_out[182]
    DIRECTION OUTPUT ;
    USE SIGNAL ;
    SHAPE ABUTMENT ;
    PORT
      LAYER met2 ;
      RECT 252.470 606.140 252.610 606.560 ;
    END
  END r0_rd_out[182]
  PIN r0_rd_out[183]
    DIRECTION OUTPUT ;
    USE SIGNAL ;
    SHAPE ABUTMENT ;
    PORT
      LAYER met2 ;
      RECT 253.850 606.140 253.990 606.560 ;
    END
  END r0_rd_out[183]
  PIN r0_rd_out[184]
    DIRECTION OUTPUT ;
    USE SIGNAL ;
    SHAPE ABUTMENT ;
    PORT
      LAYER met2 ;
      RECT 255.230 606.140 255.370 606.560 ;
    END
  END r0_rd_out[184]
  PIN r0_rd_out[185]
    DIRECTION OUTPUT ;
    USE SIGNAL ;
    SHAPE ABUTMENT ;
    PORT
      LAYER met2 ;
      RECT 256.610 606.140 256.750 606.560 ;
    END
  END r0_rd_out[185]
  PIN r0_rd_out[186]
    DIRECTION OUTPUT ;
    USE SIGNAL ;
    SHAPE ABUTMENT ;
    PORT
      LAYER met2 ;
      RECT 257.990 606.140 258.130 606.560 ;
    END
  END r0_rd_out[186]
  PIN r0_rd_out[187]
    DIRECTION OUTPUT ;
    USE SIGNAL ;
    SHAPE ABUTMENT ;
    PORT
      LAYER met2 ;
      RECT 259.370 606.140 259.510 606.560 ;
    END
  END r0_rd_out[187]
  PIN r0_rd_out[188]
    DIRECTION OUTPUT ;
    USE SIGNAL ;
    SHAPE ABUTMENT ;
    PORT
      LAYER met2 ;
      RECT 260.750 606.140 260.890 606.560 ;
    END
  END r0_rd_out[188]
  PIN r0_rd_out[189]
    DIRECTION OUTPUT ;
    USE SIGNAL ;
    SHAPE ABUTMENT ;
    PORT
      LAYER met2 ;
      RECT 262.130 606.140 262.270 606.560 ;
    END
  END r0_rd_out[189]
  PIN r0_rd_out[190]
    DIRECTION OUTPUT ;
    USE SIGNAL ;
    SHAPE ABUTMENT ;
    PORT
      LAYER met2 ;
      RECT 263.510 606.140 263.650 606.560 ;
    END
  END r0_rd_out[190]
  PIN r0_rd_out[191]
    DIRECTION OUTPUT ;
    USE SIGNAL ;
    SHAPE ABUTMENT ;
    PORT
      LAYER met2 ;
      RECT 264.890 606.140 265.030 606.560 ;
    END
  END r0_rd_out[191]
  PIN r0_rd_out[192]
    DIRECTION OUTPUT ;
    USE SIGNAL ;
    SHAPE ABUTMENT ;
    PORT
      LAYER met2 ;
      RECT 266.270 606.140 266.410 606.560 ;
    END
  END r0_rd_out[192]
  PIN w0_addr_in[0]
    DIRECTION INPUT ;
    USE SIGNAL ;
    SHAPE ABUTMENT ;
    PORT
      LAYER met3 ;
      RECT 0.000 537.050 0.900 537.350 ;
    END
  END w0_addr_in[0]
  PIN w0_addr_in[1]
    DIRECTION INPUT ;
    USE SIGNAL ;
    SHAPE ABUTMENT ;
    PORT
      LAYER met3 ;
      RECT 0.000 542.490 0.900 542.790 ;
    END
  END w0_addr_in[1]
  PIN w0_addr_in[2]
    DIRECTION INPUT ;
    USE SIGNAL ;
    SHAPE ABUTMENT ;
    PORT
      LAYER met3 ;
      RECT 0.000 547.930 0.900 548.230 ;
    END
  END w0_addr_in[2]
  PIN w0_addr_in[3]
    DIRECTION INPUT ;
    USE SIGNAL ;
    SHAPE ABUTMENT ;
    PORT
      LAYER met3 ;
      RECT 351.000 526.170 351.900 526.470 ;
    END
  END w0_addr_in[3]
  PIN r0_addr_in[0]
    DIRECTION INPUT ;
    USE SIGNAL ;
    SHAPE ABUTMENT ;
    PORT
      LAYER met3 ;
      RECT 0.000 553.370 0.900 553.670 ;
    END
  END r0_addr_in[0]
  PIN r0_addr_in[1]
    DIRECTION INPUT ;
    USE SIGNAL ;
    SHAPE ABUTMENT ;
    PORT
      LAYER met3 ;
      RECT 0.000 558.810 0.900 559.110 ;
    END
  END r0_addr_in[1]
  PIN r0_addr_in[2]
    DIRECTION INPUT ;
    USE SIGNAL ;
    SHAPE ABUTMENT ;
    PORT
      LAYER met3 ;
      RECT 0.000 564.250 0.900 564.550 ;
    END
  END r0_addr_in[2]
  PIN r0_addr_in[3]
    DIRECTION INPUT ;
    USE SIGNAL ;
    SHAPE ABUTMENT ;
    PORT
      LAYER met3 ;
      RECT 351.000 537.050 351.900 537.350 ;
    END
  END r0_addr_in[3]
  PIN w0_we_in
    DIRECTION INPUT ;
    USE SIGNAL ;
    SHAPE ABUTMENT ;
    PORT
      LAYER met2 ;
      RECT 267.650 606.140 267.790 606.560 ;
    END
  END w0_we_in
  PIN w0_ce_in
    DIRECTION INPUT ;
    USE SIGNAL ;
    SHAPE ABUTMENT ;
    PORT
      LAYER met2 ;
      RECT 269.030 606.140 269.170 606.560 ;
    END
  END w0_ce_in
  PIN w0_clk
    DIRECTION INPUT ;
    USE SIGNAL ;
    SHAPE ABUTMENT ;
    PORT
      LAYER met2 ;
      RECT 270.410 606.140 270.550 606.560 ;
    END
  END w0_clk
  PIN r0_ce_in
    DIRECTION INPUT ;
    USE SIGNAL ;
    SHAPE ABUTMENT ;
    PORT
      LAYER met2 ;
      RECT 271.790 606.140 271.930 606.560 ;
    END
  END r0_ce_in
  PIN r0_clk
    DIRECTION INPUT ;
    USE SIGNAL ;
    SHAPE ABUTMENT ;
    PORT
      LAYER met2 ;
      RECT 273.170 606.140 273.310 606.560 ;
    END
  END r0_clk
  PIN VSS
    DIRECTION INOUT ;
    USE GROUND ;
    PORT
      LAYER met4 ;
      RECT 2.160 4.080 3.360 602.480 ;
      RECT 13.040 4.080 14.240 602.480 ;
      RECT 23.920 4.080 25.120 602.480 ;
      RECT 34.800 4.080 36.000 602.480 ;
      RECT 45.680 4.080 46.880 602.480 ;
      RECT 56.560 4.080 57.760 602.480 ;
      RECT 67.440 4.080 68.640 602.480 ;
      RECT 78.320 4.080 79.520 602.480 ;
      RECT 89.200 4.080 90.400 602.480 ;
      RECT 100.080 4.080 101.280 602.480 ;
      RECT 110.960 4.080 112.160 602.480 ;
      RECT 121.840 4.080 123.040 602.480 ;
      RECT 132.720 4.080 133.920 602.480 ;
      RECT 143.600 4.080 144.800 602.480 ;
      RECT 154.480 4.080 155.680 602.480 ;
      RECT 165.360 4.080 166.560 602.480 ;
      RECT 176.240 4.080 177.440 602.480 ;
      RECT 187.120 4.080 188.320 602.480 ;
      RECT 198.000 4.080 199.200 602.480 ;
      RECT 208.880 4.080 210.080 602.480 ;
      RECT 219.760 4.080 220.960 602.480 ;
      RECT 230.640 4.080 231.840 602.480 ;
      RECT 241.520 4.080 242.720 602.480 ;
      RECT 252.400 4.080 253.600 602.480 ;
      RECT 263.280 4.080 264.480 602.480 ;
      RECT 274.160 4.080 275.360 602.480 ;
      RECT 285.040 4.080 286.240 602.480 ;
      RECT 295.920 4.080 297.120 602.480 ;
      RECT 306.800 4.080 308.000 602.480 ;
      RECT 317.680 4.080 318.880 602.480 ;
      RECT 328.560 4.080 329.760 602.480 ;
      RECT 339.440 4.080 340.640 602.480 ;
      RECT 350.320 4.080 351.520 602.480 ;
    END
  END VSS
  PIN VDD
    DIRECTION INOUT ;
    USE POWER ;
    PORT
      LAYER met4 ;
      RECT 2.160 4.080 3.360 602.480 ;
      RECT 13.040 4.080 14.240 602.480 ;
      RECT 23.920 4.080 25.120 602.480 ;
      RECT 34.800 4.080 36.000 602.480 ;
      RECT 45.680 4.080 46.880 602.480 ;
      RECT 56.560 4.080 57.760 602.480 ;
      RECT 67.440 4.080 68.640 602.480 ;
      RECT 78.320 4.080 79.520 602.480 ;
      RECT 89.200 4.080 90.400 602.480 ;
      RECT 100.080 4.080 101.280 602.480 ;
      RECT 110.960 4.080 112.160 602.480 ;
      RECT 121.840 4.080 123.040 602.480 ;
      RECT 132.720 4.080 133.920 602.480 ;
      RECT 143.600 4.080 144.800 602.480 ;
      RECT 154.480 4.080 155.680 602.480 ;
      RECT 165.360 4.080 166.560 602.480 ;
      RECT 176.240 4.080 177.440 602.480 ;
      RECT 187.120 4.080 188.320 602.480 ;
      RECT 198.000 4.080 199.200 602.480 ;
      RECT 208.880 4.080 210.080 602.480 ;
      RECT 219.760 4.080 220.960 602.480 ;
      RECT 230.640 4.080 231.840 602.480 ;
      RECT 241.520 4.080 242.720 602.480 ;
      RECT 252.400 4.080 253.600 602.480 ;
      RECT 263.280 4.080 264.480 602.480 ;
      RECT 274.160 4.080 275.360 602.480 ;
      RECT 285.040 4.080 286.240 602.480 ;
      RECT 295.920 4.080 297.120 602.480 ;
      RECT 306.800 4.080 308.000 602.480 ;
      RECT 317.680 4.080 318.880 602.480 ;
      RECT 328.560 4.080 329.760 602.480 ;
      RECT 339.440 4.080 340.640 602.480 ;
      RECT 350.320 4.080 351.520 602.480 ;
    END
  END VDD
  OBS
    LAYER met1 ;
    RECT 0 0 351.900 606.560 ;
    LAYER met2 ;
    RECT 0 0 351.900 606.560 ;
    LAYER met3 ;
    RECT 0 0 351.900 606.560 ;
    LAYER met4 ;
    RECT 0 0 351.900 606.560 ;
  END
END fakeram_193x16_1r1w

END LIBRARY
